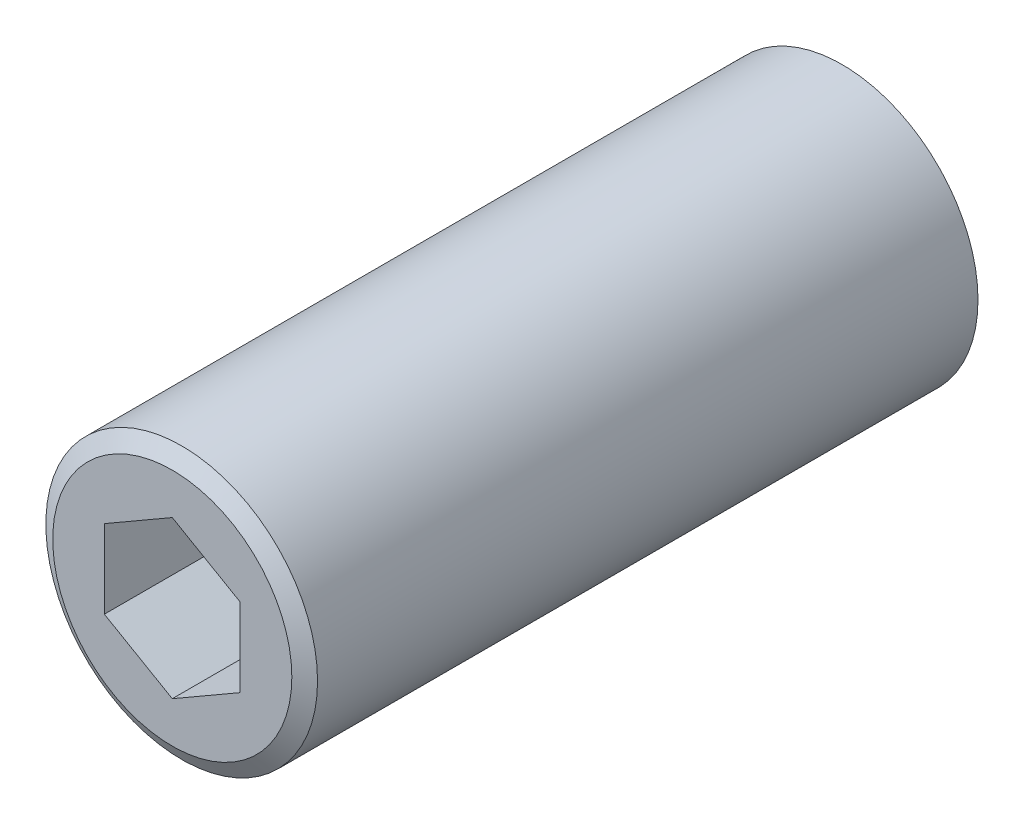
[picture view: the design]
ISO-10303-21;
HEADER;
FILE_DESCRIPTION(('STEP AP214'),'2;1');
FILE_NAME('part.step','',(''),(''),'','','');
FILE_SCHEMA(('AUTOMOTIVE_DESIGN { 1 0 10303 214 1 1 1 1 }'));
ENDSEC;
DATA;
#1=APPLICATION_CONTEXT('core data for automotive mechanical design processes');
#2=APPLICATION_PROTOCOL_DEFINITION('international standard','automotive_design',2000,#1);
#3=PRODUCT_CONTEXT('',#1,'mechanical');
#4=PRODUCT('Part','Part','',(#3));
#5=PRODUCT_RELATED_PRODUCT_CATEGORY('part','',(#4));
#6=PRODUCT_DEFINITION_FORMATION('','',#4);
#7=PRODUCT_DEFINITION_CONTEXT('part definition',#1,'design');
#8=PRODUCT_DEFINITION('design','',#6,#7);
#9=PRODUCT_DEFINITION_SHAPE('','',#8);
#10=(LENGTH_UNIT() NAMED_UNIT(*) SI_UNIT(.MILLI.,.METRE.));
#11=(NAMED_UNIT(*) PLANE_ANGLE_UNIT() SI_UNIT($,.RADIAN.));
#12=(NAMED_UNIT(*) SI_UNIT($,.STERADIAN.) SOLID_ANGLE_UNIT());
#13=UNCERTAINTY_MEASURE_WITH_UNIT(LENGTH_MEASURE(1.E-05),#10,'distance_accuracy_value','');
#14=(GEOMETRIC_REPRESENTATION_CONTEXT(3) GLOBAL_UNCERTAINTY_ASSIGNED_CONTEXT((#13)) GLOBAL_UNIT_ASSIGNED_CONTEXT((#10,
#11,#12)) REPRESENTATION_CONTEXT('',''));
#15=CARTESIAN_POINT('',(0.,0.,0.));
#16=DIRECTION('',(0.,0.,1.));
#17=DIRECTION('',(1.,0.,0.));
#18=AXIS2_PLACEMENT_3D('',#15,#16,#17);
#19=CARTESIAN_POINT('',(1.5,-6.35,0.));
#20=DIRECTION('',(-0.707106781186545,0.,0.70710678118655));
#21=DIRECTION('',(0.70710678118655,0.,0.707106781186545));
#22=AXIS2_PLACEMENT_3D('',#19,#20,#21);
#23=PLANE('',#22);
#24=CARTESIAN_POINT('',(0.,0.,-1.5));
#25=DIRECTION('',(-0.707106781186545,0.,0.70710678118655));
#26=DIRECTION('',(-0.70710678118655,0.,-0.707106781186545));
#27=AXIS2_PLACEMENT_3D('',#24,#25,#26);
#28=ELLIPSE('',#27,8.98025612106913,6.35);
#29=CARTESIAN_POINT('',(2.77,-5.71398284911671,1.27));
#30=VERTEX_POINT('',#29);
#31=CARTESIAN_POINT('',(3.,-5.59665078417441,1.5));
#32=VERTEX_POINT('',#31);
#33=EDGE_CURVE('E516',#30,#32,#28,.T.);
#34=ORIENTED_EDGE('',*,*,#33,.F.);
#35=CARTESIAN_POINT('',(0.,0.,-1.5));
#36=DIRECTION('',(-0.707106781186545,0.,0.70710678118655));
#37=DIRECTION('',(0.70710678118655,0.,0.707106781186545));
#38=AXIS2_PLACEMENT_3D('',#35,#36,#37);
#39=ELLIPSE('',#38,8.98025612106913,6.35);
#40=CARTESIAN_POINT('',(2.73216847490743,-5.73216847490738,1.2321684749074));
#41=VERTEX_POINT('',#40);
#42=EDGE_CURVE('E835',#41,#30,#39,.T.);
#43=ORIENTED_EDGE('',*,*,#42,.F.);
#44=DIRECTION('',(-0.577350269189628,0.577350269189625,-0.577350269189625));
#45=VECTOR('',#44,1.);
#46=CARTESIAN_POINT('',(2.11666666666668,-5.11666666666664,0.616666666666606));
#47=LINE('',#46,#45);
#48=CARTESIAN_POINT('',(1.49999999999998,-4.5,0.));
#49=VERTEX_POINT('',#48);
#50=EDGE_CURVE('E635',#41,#49,#47,.T.);
#51=ORIENTED_EDGE('',*,*,#50,.T.);
#52=DIRECTION('',(0.577350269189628,0.577350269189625,0.577350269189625));
#53=VECTOR('',#52,1.);
#54=CARTESIAN_POINT('',(0.883333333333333,-5.11666666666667,-0.616666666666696));
#55=LINE('',#54,#53);
#56=CARTESIAN_POINT('',(3.,-3.,1.5));
#57=VERTEX_POINT('',#56);
#58=EDGE_CURVE('E652',#49,#57,#55,.T.);
#59=ORIENTED_EDGE('',*,*,#58,.T.);
#60=DIRECTION('',(0.,1.,0.));
#61=VECTOR('',#60,1.);
#62=CARTESIAN_POINT('',(3.,-6.35,1.5));
#63=LINE('',#62,#61);
#64=EDGE_CURVE('E805',#32,#57,#63,.T.);
#65=ORIENTED_EDGE('',*,*,#64,.F.);
#66=EDGE_LOOP('',(#34,#43,#51,#59,#65));
#67=FACE_BOUND('',#66,.T.);
#68=ADVANCED_FACE('F14',(#67),#23,.F.);
#69=CARTESIAN_POINT('',(1.5,-6.35,0.));
#70=DIRECTION('',(0.707106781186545,0.,0.70710678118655));
#71=DIRECTION('',(0.70710678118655,0.,-0.707106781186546));
#72=AXIS2_PLACEMENT_3D('',#69,#70,#71);
#73=PLANE('',#72);
#74=CARTESIAN_POINT('',(0.,0.,1.5));
#75=DIRECTION('',(0.707106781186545,0.,0.70710678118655));
#76=DIRECTION('',(0.70710678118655,0.,-0.707106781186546));
#77=AXIS2_PLACEMENT_3D('',#74,#75,#76);
#78=ELLIPSE('',#77,8.98025612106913,6.35);
#79=CARTESIAN_POINT('',(0.,-6.35,1.5));
#80=VERTEX_POINT('',#79);
#81=CARTESIAN_POINT('',(0.229999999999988,-6.34583327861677,1.27));
#82=VERTEX_POINT('',#81);
#83=EDGE_CURVE('E550',#80,#82,#78,.T.);
#84=ORIENTED_EDGE('',*,*,#83,.F.);
#85=DIRECTION('',(0.,1.,0.));
#86=VECTOR('',#85,1.);
#87=CARTESIAN_POINT('',(0.,-6.35,1.5));
#88=LINE('',#87,#86);
#89=CARTESIAN_POINT('',(0.,-6.,1.5));
#90=VERTEX_POINT('',#89);
#91=EDGE_CURVE('E789',#80,#90,#88,.T.);
#92=ORIENTED_EDGE('',*,*,#91,.T.);
#93=DIRECTION('',(0.577350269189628,-0.577350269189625,-0.577350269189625));
#94=VECTOR('',#93,1.);
#95=CARTESIAN_POINT('',(1.11666666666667,-7.11666666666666,0.383333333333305));
#96=LINE('',#95,#94);
#97=CARTESIAN_POINT('',(0.340845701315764,-6.34084570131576,1.1591542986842));
#98=VERTEX_POINT('',#97);
#99=EDGE_CURVE('E625',#90,#98,#96,.T.);
#100=ORIENTED_EDGE('',*,*,#99,.T.);
#101=CARTESIAN_POINT('',(0.,0.,1.5));
#102=DIRECTION('',(0.707106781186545,0.,0.70710678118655));
#103=DIRECTION('',(-0.70710678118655,0.,0.707106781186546));
#104=AXIS2_PLACEMENT_3D('',#101,#102,#103);
#105=ELLIPSE('',#104,8.98025612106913,6.35);
#106=EDGE_CURVE('E834',#82,#98,#105,.T.);
#107=ORIENTED_EDGE('',*,*,#106,.F.);
#108=EDGE_LOOP('',(#84,#92,#100,#107));
#109=FACE_BOUND('',#108,.T.);
#110=ADVANCED_FACE('F895',(#109),#73,.F.);
#111=CARTESIAN_POINT('',(0.,0.,1.5));
#112=DIRECTION('',(0.707106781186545,0.,0.70710678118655));
#113=DIRECTION('',(0.70710678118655,0.,-0.707106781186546));
#114=AXIS2_PLACEMENT_3D('',#111,#112,#113);
#115=ELLIPSE('',#114,8.98025612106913,6.35);
#116=CARTESIAN_POINT('',(0.229999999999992,6.34583327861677,1.27));
#117=VERTEX_POINT('',#116);
#118=CARTESIAN_POINT('',(0.,6.35,1.5));
#119=VERTEX_POINT('',#118);
#120=EDGE_CURVE('E547',#117,#119,#115,.T.);
#121=ORIENTED_EDGE('',*,*,#120,.F.);
#122=CARTESIAN_POINT('',(0.340845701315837,6.34084570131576,1.15915429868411));
#123=VERTEX_POINT('',#122);
#124=EDGE_CURVE('E831',#123,#117,#105,.T.);
#125=ORIENTED_EDGE('',*,*,#124,.F.);
#126=DIRECTION('',(-0.577350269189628,-0.577350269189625,0.577350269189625));
#127=VECTOR('',#126,1.);
#128=CARTESIAN_POINT('',(-3.11666666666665,2.88333333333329,4.6166666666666));
#129=LINE('',#128,#127);
#130=CARTESIAN_POINT('',(0.,6.,1.5));
#131=VERTEX_POINT('',#130);
#132=EDGE_CURVE('E613',#123,#131,#129,.T.);
#133=ORIENTED_EDGE('',*,*,#132,.T.);
#134=EDGE_CURVE('E794',#131,#119,#88,.T.);
#135=ORIENTED_EDGE('',*,*,#134,.T.);
#136=EDGE_LOOP('',(#121,#125,#133,#135));
#137=FACE_BOUND('',#136,.T.);
#138=ADVANCED_FACE('F903',(#137),#73,.F.);
#139=CARTESIAN_POINT('',(0.,-6.35,1.5));
#140=DIRECTION('',(-0.70710678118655,0.,0.707106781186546));
#141=DIRECTION('',(0.707106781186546,0.,0.70710678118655));
#142=AXIS2_PLACEMENT_3D('',#139,#140,#141);
#143=PLANE('',#142);
#144=CARTESIAN_POINT('',(0.,0.,1.5));
#145=DIRECTION('',(-0.70710678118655,0.,0.707106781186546));
#146=DIRECTION('',(-0.707106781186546,0.,-0.70710678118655));
#147=AXIS2_PLACEMENT_3D('',#144,#145,#146);
#148=ELLIPSE('',#147,8.98025612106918,6.35);
#149=CARTESIAN_POINT('',(-0.229999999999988,-6.34583327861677,1.27));
#150=VERTEX_POINT('',#149);
#151=EDGE_CURVE('E511',#150,#80,#148,.T.);
#152=ORIENTED_EDGE('',*,*,#151,.F.);
#153=CARTESIAN_POINT('',(0.,0.,1.5));
#154=DIRECTION('',(-0.70710678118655,0.,0.707106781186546));
#155=DIRECTION('',(0.707106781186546,0.,0.70710678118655));
#156=AXIS2_PLACEMENT_3D('',#153,#154,#155);
#157=ELLIPSE('',#156,8.98025612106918,6.35);
#158=CARTESIAN_POINT('',(-0.34084570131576,-6.34084570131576,1.1591542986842));
#159=VERTEX_POINT('',#158);
#160=EDGE_CURVE('E827',#159,#150,#157,.T.);
#161=ORIENTED_EDGE('',*,*,#160,.F.);
#162=DIRECTION('',(0.577350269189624,0.577350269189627,0.577350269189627));
#163=VECTOR('',#162,1.);
#164=CARTESIAN_POINT('',(-0.116666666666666,-6.11666666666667,1.38333333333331));
#165=LINE('',#164,#163);
#166=EDGE_CURVE('E628',#159,#90,#165,.T.);
#167=ORIENTED_EDGE('',*,*,#166,.T.);
#168=ORIENTED_EDGE('',*,*,#91,.F.);
#169=EDGE_LOOP('',(#152,#161,#167,#168));
#170=FACE_BOUND('',#169,.T.);
#171=ADVANCED_FACE('F1345',(#170),#143,.F.);
#172=CARTESIAN_POINT('',(0.,0.,1.5));
#173=DIRECTION('',(-0.70710678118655,0.,0.707106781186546));
#174=DIRECTION('',(-0.707106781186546,0.,-0.70710678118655));
#175=AXIS2_PLACEMENT_3D('',#172,#173,#174);
#176=ELLIPSE('',#175,8.98025612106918,6.35);
#177=CARTESIAN_POINT('',(-0.229999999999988,6.34583327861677,1.27));
#178=VERTEX_POINT('',#177);
#179=EDGE_CURVE('E508',#119,#178,#176,.T.);
#180=ORIENTED_EDGE('',*,*,#179,.F.);
#181=ORIENTED_EDGE('',*,*,#134,.F.);
#182=DIRECTION('',(-0.577350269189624,0.577350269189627,-0.577350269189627));
#183=VECTOR('',#182,1.);
#184=CARTESIAN_POINT('',(4.11666666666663,1.88333333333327,5.6166666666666));
#185=LINE('',#184,#183);
#186=CARTESIAN_POINT('',(-0.340845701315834,6.34084570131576,1.15915429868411));
#187=VERTEX_POINT('',#186);
#188=EDGE_CURVE('E616',#131,#187,#185,.T.);
#189=ORIENTED_EDGE('',*,*,#188,.T.);
#190=EDGE_CURVE('E830',#178,#187,#157,.T.);
#191=ORIENTED_EDGE('',*,*,#190,.F.);
#192=EDGE_LOOP('',(#180,#181,#189,#191));
#193=FACE_BOUND('',#192,.T.);
#194=ADVANCED_FACE('F1341',(#193),#143,.F.);
#195=CARTESIAN_POINT('',(-1.5,-6.35,0.));
#196=DIRECTION('',(0.707106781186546,0.,0.707106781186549));
#197=DIRECTION('',(0.707106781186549,0.,-0.707106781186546));
#198=AXIS2_PLACEMENT_3D('',#195,#196,#197);
#199=PLANE('',#198);
#200=CARTESIAN_POINT('',(0.,0.,-1.5));
#201=DIRECTION('',(0.707106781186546,0.,0.707106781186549));
#202=DIRECTION('',(0.707106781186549,0.,-0.707106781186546));
#203=AXIS2_PLACEMENT_3D('',#200,#201,#202);
#204=ELLIPSE('',#203,8.98025612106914,6.35);
#205=CARTESIAN_POINT('',(-3.,-5.59665078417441,1.5));
#206=VERTEX_POINT('',#205);
#207=CARTESIAN_POINT('',(-2.77,-5.71398284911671,1.27));
#208=VERTEX_POINT('',#207);
#209=EDGE_CURVE('E37',#206,#208,#204,.T.);
#210=ORIENTED_EDGE('',*,*,#209,.F.);
#211=DIRECTION('',(0.,1.,0.));
#212=VECTOR('',#211,1.);
#213=CARTESIAN_POINT('',(-3.,-6.35,1.5));
#214=LINE('',#213,#212);
#215=CARTESIAN_POINT('',(-3.,-3.,1.5));
#216=VERTEX_POINT('',#215);
#217=EDGE_CURVE('E795',#206,#216,#214,.T.);
#218=ORIENTED_EDGE('',*,*,#217,.T.);
#219=DIRECTION('',(0.577350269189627,-0.577350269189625,-0.577350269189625));
#220=VECTOR('',#219,1.);
#221=CARTESIAN_POINT('',(-0.883333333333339,-5.11666666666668,-0.616666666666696));
#222=LINE('',#221,#220);
#223=CARTESIAN_POINT('',(-1.5,-4.49999999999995,0.));
#224=VERTEX_POINT('',#223);
#225=EDGE_CURVE('E664',#216,#224,#222,.T.);
#226=ORIENTED_EDGE('',*,*,#225,.T.);
#227=DIRECTION('',(-0.577350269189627,-0.577350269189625,0.577350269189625));
#228=VECTOR('',#227,1.);
#229=CARTESIAN_POINT('',(-2.11666666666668,-5.11666666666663,0.616666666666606));
#230=LINE('',#229,#228);
#231=CARTESIAN_POINT('',(-2.73216847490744,-5.73216847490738,1.2321684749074));
#232=VERTEX_POINT('',#231);
#233=EDGE_CURVE('E646',#224,#232,#230,.T.);
#234=ORIENTED_EDGE('',*,*,#233,.T.);
#235=CARTESIAN_POINT('',(0.,0.,-1.5));
#236=DIRECTION('',(0.707106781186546,0.,0.707106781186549));
#237=DIRECTION('',(-0.707106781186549,0.,0.707106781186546));
#238=AXIS2_PLACEMENT_3D('',#235,#236,#237);
#239=ELLIPSE('',#238,8.98025612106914,6.35);
#240=EDGE_CURVE('E826',#208,#232,#239,.T.);
#241=ORIENTED_EDGE('',*,*,#240,.F.);
#242=EDGE_LOOP('',(#210,#218,#226,#234,#241));
#243=FACE_BOUND('',#242,.T.);
#244=ADVANCED_FACE('F1335',(#243),#199,.F.);
#245=CARTESIAN_POINT('',(-3.,-6.35,1.5));
#246=DIRECTION('',(-0.707106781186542,0.,0.707106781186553));
#247=DIRECTION('',(0.707106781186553,0.,0.707106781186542));
#248=AXIS2_PLACEMENT_3D('',#245,#246,#247);
#249=PLANE('',#248);
#250=CARTESIAN_POINT('',(0.,0.,4.5));
#251=DIRECTION('',(-0.707106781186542,0.,0.707106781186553));
#252=DIRECTION('',(-0.707106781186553,0.,-0.707106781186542));
#253=AXIS2_PLACEMENT_3D('',#250,#251,#252);
#254=ELLIPSE('',#253,8.98025612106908,6.35);
#255=CARTESIAN_POINT('',(-3.23,-5.46713819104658,1.27));
#256=VERTEX_POINT('',#255);
#257=EDGE_CURVE('E543',#256,#206,#254,.T.);
#258=ORIENTED_EDGE('',*,*,#257,.F.);
#259=CARTESIAN_POINT('',(0.,0.,4.5));
#260=DIRECTION('',(-0.707106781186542,0.,0.707106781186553));
#261=DIRECTION('',(0.707106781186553,0.,0.707106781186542));
#262=AXIS2_PLACEMENT_3D('',#259,#260,#261);
#263=ELLIPSE('',#262,8.98025612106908,6.35);
#264=CARTESIAN_POINT('',(-4.49012806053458,-4.49012806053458,0.00987193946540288));
#265=VERTEX_POINT('',#264);
#266=EDGE_CURVE('E819',#265,#256,#263,.T.);
#267=ORIENTED_EDGE('',*,*,#266,.F.);
#268=DIRECTION('',(0.577350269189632,0.577350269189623,0.577350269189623));
#269=VECTOR('',#268,1.);
#270=CARTESIAN_POINT('',(-4.11666666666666,-4.11666666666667,0.383333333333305));
#271=LINE('',#270,#269);
#272=EDGE_CURVE('E666',#265,#216,#271,.T.);
#273=ORIENTED_EDGE('',*,*,#272,.T.);
#274=ORIENTED_EDGE('',*,*,#217,.F.);
#275=EDGE_LOOP('',(#258,#267,#273,#274));
#276=FACE_BOUND('',#275,.T.);
#277=ADVANCED_FACE('F1172',(#276),#249,.F.);
#278=CARTESIAN_POINT('',(-4.5,-6.35,0.));
#279=DIRECTION('',(0.707106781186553,0.,0.707106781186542));
#280=DIRECTION('',(0.707106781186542,0.,-0.707106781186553));
#281=AXIS2_PLACEMENT_3D('',#278,#279,#280);
#282=PLANE('',#281);
#283=CARTESIAN_POINT('',(0.,0.,-4.5));
#284=DIRECTION('',(0.707106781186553,0.,0.707106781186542));
#285=DIRECTION('',(0.707106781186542,0.,-0.707106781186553));
#286=AXIS2_PLACEMENT_3D('',#283,#284,#285);
#287=ELLIPSE('',#286,8.98025612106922,6.35);
#288=CARTESIAN_POINT('',(-5.77,2.65133928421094,1.27));
#289=VERTEX_POINT('',#288);
#290=CARTESIAN_POINT('',(-6.,2.07906228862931,1.5));
#291=VERTEX_POINT('',#290);
#292=EDGE_CURVE('E540',#289,#291,#287,.T.);
#293=ORIENTED_EDGE('',*,*,#292,.F.);
#294=CARTESIAN_POINT('',(0.,0.,-4.5));
#295=DIRECTION('',(0.707106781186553,0.,0.707106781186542));
#296=DIRECTION('',(-0.707106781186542,0.,0.707106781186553));
#297=AXIS2_PLACEMENT_3D('',#294,#295,#296);
#298=ELLIPSE('',#297,8.98025612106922,6.35);
#299=CARTESIAN_POINT('',(-5.73216847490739,2.73216847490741,1.2321684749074));
#300=VERTEX_POINT('',#299);
#301=EDGE_CURVE('E815',#300,#289,#298,.T.);
#302=ORIENTED_EDGE('',*,*,#301,.F.);
#303=DIRECTION('',(0.57735026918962,-0.577350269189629,-0.577350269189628));
#304=VECTOR('',#303,1.);
#305=CARTESIAN_POINT('',(-1.88333333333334,-1.1166666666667,-2.6166666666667));
#306=LINE('',#305,#304);
#307=CARTESIAN_POINT('',(-4.5,1.49999999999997,0.));
#308=VERTEX_POINT('',#307);
#309=EDGE_CURVE('E783',#300,#308,#306,.T.);
#310=ORIENTED_EDGE('',*,*,#309,.T.);
#311=DIRECTION('',(-0.57735026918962,-0.577350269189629,0.577350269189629));
#312=VECTOR('',#311,1.);
#313=CARTESIAN_POINT('',(-7.11666666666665,-1.11666666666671,2.6166666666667));
#314=LINE('',#313,#312);
#315=CARTESIAN_POINT('',(-6.,0.,1.5));
#316=VERTEX_POINT('',#315);
#317=EDGE_CURVE('E754',#308,#316,#314,.T.);
#318=ORIENTED_EDGE('',*,*,#317,.T.);
#319=DIRECTION('',(0.,1.,0.));
#320=VECTOR('',#319,1.);
#321=CARTESIAN_POINT('',(-6.,-6.35,1.5));
#322=LINE('',#321,#320);
#323=EDGE_CURVE('E801',#316,#291,#322,.T.);
#324=ORIENTED_EDGE('',*,*,#323,.T.);
#325=EDGE_LOOP('',(#293,#302,#310,#318,#324));
#326=FACE_BOUND('',#325,.T.);
#327=ADVANCED_FACE('F1219',(#326),#282,.F.);
#328=CARTESIAN_POINT('',(0.,0.,-4.5));
#329=DIRECTION('',(0.707106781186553,0.,0.707106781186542));
#330=DIRECTION('',(0.707106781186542,0.,-0.707106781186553));
#331=AXIS2_PLACEMENT_3D('',#328,#329,#330);
#332=ELLIPSE('',#331,8.98025612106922,6.35);
#333=CARTESIAN_POINT('',(-6.,-2.07906228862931,1.5));
#334=VERTEX_POINT('',#333);
#335=CARTESIAN_POINT('',(-5.77,-2.65133928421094,1.27));
#336=VERTEX_POINT('',#335);
#337=EDGE_CURVE('E534',#334,#336,#332,.T.);
#338=ORIENTED_EDGE('',*,*,#337,.F.);
#339=EDGE_CURVE('E799',#334,#316,#322,.T.);
#340=ORIENTED_EDGE('',*,*,#339,.T.);
#341=DIRECTION('',(0.57735026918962,-0.577350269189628,-0.577350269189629));
#342=VECTOR('',#341,1.);
#343=CARTESIAN_POINT('',(-2.88333333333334,-3.11666666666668,-1.6166666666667));
#344=LINE('',#343,#342);
#345=CARTESIAN_POINT('',(-4.5,-1.5,0.));
#346=VERTEX_POINT('',#345);
#347=EDGE_CURVE('E722',#316,#346,#344,.T.);
#348=ORIENTED_EDGE('',*,*,#347,.T.);
#349=DIRECTION('',(-0.57735026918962,-0.577350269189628,0.577350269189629));
#350=VECTOR('',#349,1.);
#351=CARTESIAN_POINT('',(-6.11666666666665,-3.11666666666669,1.6166666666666));
#352=LINE('',#351,#350);
#353=CARTESIAN_POINT('',(-5.73216847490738,-2.73216847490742,1.2321684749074));
#354=VERTEX_POINT('',#353);
#355=EDGE_CURVE('E693',#346,#354,#352,.T.);
#356=ORIENTED_EDGE('',*,*,#355,.T.);
#357=EDGE_CURVE('E818',#336,#354,#298,.T.);
#358=ORIENTED_EDGE('',*,*,#357,.F.);
#359=EDGE_LOOP('',(#338,#340,#348,#356,#358));
#360=FACE_BOUND('',#359,.T.);
#361=ADVANCED_FACE('F1025',(#360),#282,.F.);
#362=CARTESIAN_POINT('',(-6.,-6.35,1.5));
#363=DIRECTION('',(-0.707106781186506,0.,0.70710678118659));
#364=DIRECTION('',(0.70710678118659,0.,0.707106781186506));
#365=AXIS2_PLACEMENT_3D('',#362,#363,#364);
#366=PLANE('',#365);
#367=CARTESIAN_POINT('',(0.,0.,7.4999999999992));
#368=DIRECTION('',(-0.707106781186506,0.,0.70710678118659));
#369=DIRECTION('',(-0.70710678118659,0.,-0.707106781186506));
#370=AXIS2_PLACEMENT_3D('',#367,#368,#369);
#371=ELLIPSE('',#370,8.98025612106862,6.35);
#372=CARTESIAN_POINT('',(-6.23,1.22865780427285,1.27));
#373=VERTEX_POINT('',#372);
#374=EDGE_CURVE('E537',#291,#373,#371,.T.);
#375=ORIENTED_EDGE('',*,*,#374,.F.);
#376=ORIENTED_EDGE('',*,*,#323,.F.);
#377=DIRECTION('',(-0.577350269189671,0.577350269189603,-0.577350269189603));
#378=VECTOR('',#377,1.);
#379=CARTESIAN_POINT('',(-3.8833333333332,-2.11666666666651,3.6166666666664));
#380=LINE('',#379,#378);
#381=CARTESIAN_POINT('',(-6.34084570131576,0.340845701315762,1.1591542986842));
#382=VERTEX_POINT('',#381);
#383=EDGE_CURVE('E757',#316,#382,#380,.T.);
#384=ORIENTED_EDGE('',*,*,#383,.T.);
#385=CARTESIAN_POINT('',(0.,0.,7.4999999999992));
#386=DIRECTION('',(-0.707106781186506,0.,0.70710678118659));
#387=DIRECTION('',(0.70710678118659,0.,0.707106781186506));
#388=AXIS2_PLACEMENT_3D('',#385,#386,#387);
#389=ELLIPSE('',#388,8.98025612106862,6.35);
#390=EDGE_CURVE('E851',#373,#382,#389,.T.);
#391=ORIENTED_EDGE('',*,*,#390,.F.);
#392=EDGE_LOOP('',(#375,#376,#384,#391));
#393=FACE_BOUND('',#392,.T.);
#394=ADVANCED_FACE('F1221',(#393),#366,.F.);
#395=CARTESIAN_POINT('',(0.,0.,7.4999999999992));
#396=DIRECTION('',(-0.707106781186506,0.,0.70710678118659));
#397=DIRECTION('',(-0.70710678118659,0.,-0.707106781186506));
#398=AXIS2_PLACEMENT_3D('',#395,#396,#397);
#399=ELLIPSE('',#398,8.98025612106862,6.35);
#400=CARTESIAN_POINT('',(-6.23,-1.22865780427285,1.27));
#401=VERTEX_POINT('',#400);
#402=EDGE_CURVE('E531',#401,#334,#399,.T.);
#403=ORIENTED_EDGE('',*,*,#402,.F.);
#404=CARTESIAN_POINT('',(-6.34084570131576,-0.340845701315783,1.1591542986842));
#405=VERTEX_POINT('',#404);
#406=EDGE_CURVE('E849',#405,#401,#389,.T.);
#407=ORIENTED_EDGE('',*,*,#406,.F.);
#408=DIRECTION('',(0.577350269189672,0.577350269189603,0.577350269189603));
#409=VECTOR('',#408,1.);
#410=CARTESIAN_POINT('',(-8.1166666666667,-2.11666666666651,-0.616666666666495));
#411=LINE('',#410,#409);
#412=EDGE_CURVE('E724',#405,#316,#411,.T.);
#413=ORIENTED_EDGE('',*,*,#412,.T.);
#414=ORIENTED_EDGE('',*,*,#339,.F.);
#415=EDGE_LOOP('',(#403,#407,#413,#414));
#416=FACE_BOUND('',#415,.T.);
#417=ADVANCED_FACE('F1021',(#416),#366,.F.);
#418=CARTESIAN_POINT('',(6.,-6.35,1.5));
#419=DIRECTION('',(0.707106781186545,0.,0.70710678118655));
#420=DIRECTION('',(0.70710678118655,0.,-0.707106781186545));
#421=AXIS2_PLACEMENT_3D('',#418,#419,#420);
#422=PLANE('',#421);
#423=CARTESIAN_POINT('',(0.,0.,7.5));
#424=DIRECTION('',(0.707106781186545,0.,0.70710678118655));
#425=DIRECTION('',(0.70710678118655,0.,-0.707106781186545));
#426=AXIS2_PLACEMENT_3D('',#423,#424,#425);
#427=ELLIPSE('',#426,8.98025612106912,6.35);
#428=CARTESIAN_POINT('',(6.23,1.22865780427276,1.27));
#429=VERTEX_POINT('',#428);
#430=CARTESIAN_POINT('',(6.,2.07906228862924,1.5));
#431=VERTEX_POINT('',#430);
#432=EDGE_CURVE('E528',#429,#431,#427,.T.);
#433=ORIENTED_EDGE('',*,*,#432,.F.);
#434=CARTESIAN_POINT('',(0.,0.,7.5));
#435=DIRECTION('',(0.707106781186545,0.,0.70710678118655));
#436=DIRECTION('',(-0.70710678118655,0.,0.707106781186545));
#437=AXIS2_PLACEMENT_3D('',#434,#435,#436);
#438=ELLIPSE('',#437,8.98025612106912,6.35);
#439=CARTESIAN_POINT('',(6.34084570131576,0.340845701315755,1.1591542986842));
#440=VERTEX_POINT('',#439);
#441=EDGE_CURVE('E850',#440,#429,#438,.T.);
#442=ORIENTED_EDGE('',*,*,#441,.F.);
#443=DIRECTION('',(-0.577350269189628,-0.577350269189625,0.577350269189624));
#444=VECTOR('',#443,1.);
#445=CARTESIAN_POINT('',(3.88333333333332,-2.11666666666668,3.6166666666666));
#446=LINE('',#445,#444);
#447=CARTESIAN_POINT('',(6.,0.,1.5));
#448=VERTEX_POINT('',#447);
#449=EDGE_CURVE('E733',#440,#448,#446,.T.);
#450=ORIENTED_EDGE('',*,*,#449,.T.);
#451=DIRECTION('',(0.,1.,0.));
#452=VECTOR('',#451,1.);
#453=CARTESIAN_POINT('',(6.,-6.35,1.5));
#454=LINE('',#453,#452);
#455=EDGE_CURVE('E804',#448,#431,#454,.T.);
#456=ORIENTED_EDGE('',*,*,#455,.T.);
#457=EDGE_LOOP('',(#433,#442,#450,#456));
#458=FACE_BOUND('',#457,.T.);
#459=ADVANCED_FACE('F1917',(#458),#422,.F.);
#460=CARTESIAN_POINT('',(0.,0.,7.5));
#461=DIRECTION('',(0.707106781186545,0.,0.70710678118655));
#462=DIRECTION('',(0.70710678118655,0.,-0.707106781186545));
#463=AXIS2_PLACEMENT_3D('',#460,#461,#462);
#464=ELLIPSE('',#463,8.98025612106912,6.35);
#465=CARTESIAN_POINT('',(6.,-2.07906228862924,1.5));
#466=VERTEX_POINT('',#465);
#467=CARTESIAN_POINT('',(6.23,-1.22865780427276,1.27));
#468=VERTEX_POINT('',#467);
#469=EDGE_CURVE('E522',#466,#468,#464,.T.);
#470=ORIENTED_EDGE('',*,*,#469,.F.);
#471=EDGE_CURVE('E802',#466,#448,#454,.T.);
#472=ORIENTED_EDGE('',*,*,#471,.T.);
#473=DIRECTION('',(0.577350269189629,-0.577350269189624,-0.577350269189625));
#474=VECTOR('',#473,1.);
#475=CARTESIAN_POINT('',(8.11666666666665,-2.11666666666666,-0.616666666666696));
#476=LINE('',#475,#474);
#477=CARTESIAN_POINT('',(6.34084570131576,-0.340845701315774,1.1591542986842));
#478=VERTEX_POINT('',#477);
#479=EDGE_CURVE('E702',#448,#478,#476,.T.);
#480=ORIENTED_EDGE('',*,*,#479,.T.);
#481=EDGE_CURVE('E846',#468,#478,#438,.T.);
#482=ORIENTED_EDGE('',*,*,#481,.F.);
#483=EDGE_LOOP('',(#470,#472,#480,#482));
#484=FACE_BOUND('',#483,.T.);
#485=ADVANCED_FACE('F1913',(#484),#422,.F.);
#486=CARTESIAN_POINT('',(4.5,-6.35,0.));
#487=DIRECTION('',(-0.70710678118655,0.,0.707106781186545));
#488=DIRECTION('',(0.707106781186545,0.,0.70710678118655));
#489=AXIS2_PLACEMENT_3D('',#486,#487,#488);
#490=PLANE('',#489);
#491=CARTESIAN_POINT('',(0.,0.,-4.5));
#492=DIRECTION('',(-0.70710678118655,0.,0.707106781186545));
#493=DIRECTION('',(-0.707106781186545,0.,-0.70710678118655));
#494=AXIS2_PLACEMENT_3D('',#491,#492,#493);
#495=ELLIPSE('',#494,8.98025612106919,6.35);
#496=CARTESIAN_POINT('',(5.77,2.65133928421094,1.27));
#497=VERTEX_POINT('',#496);
#498=EDGE_CURVE('E525',#431,#497,#495,.T.);
#499=ORIENTED_EDGE('',*,*,#498,.F.);
#500=ORIENTED_EDGE('',*,*,#455,.F.);
#501=DIRECTION('',(-0.577350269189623,0.577350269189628,-0.577350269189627));
#502=VECTOR('',#501,1.);
#503=CARTESIAN_POINT('',(7.11666666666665,-1.1166666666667,2.61666666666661));
#504=LINE('',#503,#502);
#505=CARTESIAN_POINT('',(4.5,1.49999999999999,0.));
#506=VERTEX_POINT('',#505);
#507=EDGE_CURVE('E730',#448,#506,#504,.T.);
#508=ORIENTED_EDGE('',*,*,#507,.T.);
#509=DIRECTION('',(0.577350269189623,0.577350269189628,0.577350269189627));
#510=VECTOR('',#509,1.);
#511=CARTESIAN_POINT('',(1.88333333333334,-1.11666666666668,-2.6166666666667));
#512=LINE('',#511,#510);
#513=CARTESIAN_POINT('',(5.73216847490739,2.73216847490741,1.2321684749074));
#514=VERTEX_POINT('',#513);
#515=EDGE_CURVE('E763',#506,#514,#512,.T.);
#516=ORIENTED_EDGE('',*,*,#515,.T.);
#517=CARTESIAN_POINT('',(0.,0.,-4.5));
#518=DIRECTION('',(-0.70710678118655,0.,0.707106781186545));
#519=DIRECTION('',(0.707106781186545,0.,0.70710678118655));
#520=AXIS2_PLACEMENT_3D('',#517,#518,#519);
#521=ELLIPSE('',#520,8.98025612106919,6.35);
#522=EDGE_CURVE('E814',#497,#514,#521,.T.);
#523=ORIENTED_EDGE('',*,*,#522,.F.);
#524=EDGE_LOOP('',(#499,#500,#508,#516,#523));
#525=FACE_BOUND('',#524,.T.);
#526=ADVANCED_FACE('F1058',(#525),#490,.F.);
#527=CARTESIAN_POINT('',(0.,0.,-4.5));
#528=DIRECTION('',(-0.70710678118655,0.,0.707106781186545));
#529=DIRECTION('',(-0.707106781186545,0.,-0.70710678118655));
#530=AXIS2_PLACEMENT_3D('',#527,#528,#529);
#531=ELLIPSE('',#530,8.98025612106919,6.35);
#532=CARTESIAN_POINT('',(5.77,-2.65133928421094,1.27));
#533=VERTEX_POINT('',#532);
#534=EDGE_CURVE('E519',#533,#466,#531,.T.);
#535=ORIENTED_EDGE('',*,*,#534,.F.);
#536=CARTESIAN_POINT('',(5.73216847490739,-2.73216847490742,1.2321684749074));
#537=VERTEX_POINT('',#536);
#538=EDGE_CURVE('E811',#537,#533,#521,.T.);
#539=ORIENTED_EDGE('',*,*,#538,.F.);
#540=DIRECTION('',(-0.577350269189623,0.577350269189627,-0.577350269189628));
#541=VECTOR('',#540,1.);
#542=CARTESIAN_POINT('',(6.11666666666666,-3.11666666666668,1.6166666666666));
#543=LINE('',#542,#541);
#544=CARTESIAN_POINT('',(4.5,-1.5,0.));
#545=VERTEX_POINT('',#544);
#546=EDGE_CURVE('E672',#537,#545,#543,.T.);
#547=ORIENTED_EDGE('',*,*,#546,.T.);
#548=DIRECTION('',(0.577350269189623,0.577350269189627,0.577350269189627));
#549=VECTOR('',#548,1.);
#550=CARTESIAN_POINT('',(2.88333333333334,-3.11666666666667,-1.6166666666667));
#551=LINE('',#550,#549);
#552=EDGE_CURVE('E699',#545,#448,#551,.T.);
#553=ORIENTED_EDGE('',*,*,#552,.T.);
#554=ORIENTED_EDGE('',*,*,#471,.F.);
#555=EDGE_LOOP('',(#535,#539,#547,#553,#554));
#556=FACE_BOUND('',#555,.T.);
#557=ADVANCED_FACE('F958',(#556),#490,.F.);
#558=CARTESIAN_POINT('',(3.,-6.35,1.5));
#559=DIRECTION('',(0.707106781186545,0.,0.70710678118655));
#560=DIRECTION('',(0.70710678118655,0.,-0.707106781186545));
#561=AXIS2_PLACEMENT_3D('',#558,#559,#560);
#562=PLANE('',#561);
#563=CARTESIAN_POINT('',(0.,0.,4.5));
#564=DIRECTION('',(0.707106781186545,0.,0.70710678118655));
#565=DIRECTION('',(0.70710678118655,0.,-0.707106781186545));
#566=AXIS2_PLACEMENT_3D('',#563,#564,#565);
#567=ELLIPSE('',#566,8.98025612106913,6.35);
#568=CARTESIAN_POINT('',(3.23,-5.46713819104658,1.27));
#569=VERTEX_POINT('',#568);
#570=EDGE_CURVE('E513',#32,#569,#567,.T.);
#571=ORIENTED_EDGE('',*,*,#570,.F.);
#572=ORIENTED_EDGE('',*,*,#64,.T.);
#573=DIRECTION('',(0.577350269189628,-0.577350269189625,-0.577350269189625));
#574=VECTOR('',#573,1.);
#575=CARTESIAN_POINT('',(4.11666666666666,-4.11666666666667,0.383333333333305));
#576=LINE('',#575,#574);
#577=CARTESIAN_POINT('',(4.49012806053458,-4.49012806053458,0.00987193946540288));
#578=VERTEX_POINT('',#577);
#579=EDGE_CURVE('E869',#57,#578,#576,.T.);
#580=ORIENTED_EDGE('',*,*,#579,.T.);
#581=CARTESIAN_POINT('',(0.,0.,4.5));
#582=DIRECTION('',(0.707106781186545,0.,0.70710678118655));
#583=DIRECTION('',(-0.70710678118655,0.,0.707106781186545));
#584=AXIS2_PLACEMENT_3D('',#581,#582,#583);
#585=ELLIPSE('',#584,8.98025612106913,6.35);
#586=EDGE_CURVE('E810',#569,#578,#585,.T.);
#587=ORIENTED_EDGE('',*,*,#586,.F.);
#588=EDGE_LOOP('',(#571,#572,#580,#587));
#589=FACE_BOUND('',#588,.T.);
#590=ADVANCED_FACE('F911',(#589),#562,.F.);
#591=CARTESIAN_POINT('',(0.,0.,-1.5));
#592=DIRECTION('',(-0.707106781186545,0.,0.70710678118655));
#593=DIRECTION('',(-0.70710678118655,0.,-0.707106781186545));
#594=AXIS2_PLACEMENT_3D('',#591,#592,#593);
#595=ELLIPSE('',#594,8.98025612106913,6.35);
#596=CARTESIAN_POINT('',(3.,5.59665078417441,1.5));
#597=VERTEX_POINT('',#596);
#598=CARTESIAN_POINT('',(2.77,5.71398284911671,1.27));
#599=VERTEX_POINT('',#598);
#600=EDGE_CURVE('E499',#597,#599,#595,.T.);
#601=ORIENTED_EDGE('',*,*,#600,.F.);
#602=CARTESIAN_POINT('',(3.,3.,1.5));
#603=VERTEX_POINT('',#602);
#604=EDGE_CURVE('E788',#603,#597,#63,.T.);
#605=ORIENTED_EDGE('',*,*,#604,.F.);
#606=DIRECTION('',(-0.577350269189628,0.577350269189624,-0.577350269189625));
#607=VECTOR('',#606,1.);
#608=CARTESIAN_POINT('',(5.11666666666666,0.883333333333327,3.6166666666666));
#609=LINE('',#608,#607);
#610=CARTESIAN_POINT('',(1.50000000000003,4.5,0.));
#611=VERTEX_POINT('',#610);
#612=EDGE_CURVE('E556',#603,#611,#609,.T.);
#613=ORIENTED_EDGE('',*,*,#612,.T.);
#614=DIRECTION('',(0.577350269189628,0.577350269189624,0.577350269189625));
#615=VECTOR('',#614,1.);
#616=CARTESIAN_POINT('',(-2.11666666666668,0.883333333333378,-3.6166666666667));
#617=LINE('',#616,#615);
#618=CARTESIAN_POINT('',(2.73216847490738,5.73216847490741,1.23216847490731));
#619=VERTEX_POINT('',#618);
#620=EDGE_CURVE('E594',#611,#619,#617,.T.);
#621=ORIENTED_EDGE('',*,*,#620,.T.);
#622=EDGE_CURVE('E838',#599,#619,#39,.T.);
#623=ORIENTED_EDGE('',*,*,#622,.F.);
#624=EDGE_LOOP('',(#601,#605,#613,#621,#623));
#625=FACE_BOUND('',#624,.T.);
#626=ADVANCED_FACE('F898',(#625),#23,.F.);
#627=CARTESIAN_POINT('',(0.,0.,-1.5));
#628=DIRECTION('',(0.707106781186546,0.,0.707106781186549));
#629=DIRECTION('',(0.707106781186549,0.,-0.707106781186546));
#630=AXIS2_PLACEMENT_3D('',#627,#628,#629);
#631=ELLIPSE('',#630,8.98025612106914,6.35);
#632=CARTESIAN_POINT('',(-2.77,5.71398284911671,1.27));
#633=VERTEX_POINT('',#632);
#634=CARTESIAN_POINT('',(-3.,5.59665078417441,1.5));
#635=VERTEX_POINT('',#634);
#636=EDGE_CURVE('E505',#633,#635,#631,.T.);
#637=ORIENTED_EDGE('',*,*,#636,.F.);
#638=CARTESIAN_POINT('',(-2.73216847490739,5.7321684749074,1.23216847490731));
#639=VERTEX_POINT('',#638);
#640=EDGE_CURVE('E823',#639,#633,#239,.T.);
#641=ORIENTED_EDGE('',*,*,#640,.F.);
#642=DIRECTION('',(0.577350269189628,-0.577350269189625,-0.577350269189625));
#643=VECTOR('',#642,1.);
#644=CARTESIAN_POINT('',(2.11666666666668,0.883333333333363,-3.6166666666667));
#645=LINE('',#644,#643);
#646=CARTESIAN_POINT('',(-1.5,4.5,0.));
#647=VERTEX_POINT('',#646);
#648=EDGE_CURVE('E605',#639,#647,#645,.T.);
#649=ORIENTED_EDGE('',*,*,#648,.T.);
#650=DIRECTION('',(-0.577350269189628,-0.577350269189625,0.577350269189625));
#651=VECTOR('',#650,1.);
#652=CARTESIAN_POINT('',(-5.11666666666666,0.883333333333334,3.6166666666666));
#653=LINE('',#652,#651);
#654=CARTESIAN_POINT('',(-3.,3.,1.5));
#655=VERTEX_POINT('',#654);
#656=EDGE_CURVE('E584',#647,#655,#653,.T.);
#657=ORIENTED_EDGE('',*,*,#656,.T.);
#658=EDGE_CURVE('E798',#655,#635,#214,.T.);
#659=ORIENTED_EDGE('',*,*,#658,.T.);
#660=EDGE_LOOP('',(#637,#641,#649,#657,#659));
#661=FACE_BOUND('',#660,.T.);
#662=ADVANCED_FACE('F910',(#661),#199,.F.);
#663=CARTESIAN_POINT('',(0.,0.,4.5));
#664=DIRECTION('',(-0.707106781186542,0.,0.707106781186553));
#665=DIRECTION('',(-0.707106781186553,0.,-0.707106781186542));
#666=AXIS2_PLACEMENT_3D('',#663,#664,#665);
#667=ELLIPSE('',#666,8.98025612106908,6.35);
#668=CARTESIAN_POINT('',(-3.23,5.46713819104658,1.27));
#669=VERTEX_POINT('',#668);
#670=EDGE_CURVE('E502',#635,#669,#667,.T.);
#671=ORIENTED_EDGE('',*,*,#670,.F.);
#672=ORIENTED_EDGE('',*,*,#658,.F.);
#673=DIRECTION('',(-0.577350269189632,0.577350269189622,-0.577350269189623));
#674=VECTOR('',#673,1.);
#675=CARTESIAN_POINT('',(0.116666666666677,-0.116666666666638,4.6166666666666));
#676=LINE('',#675,#674);
#677=CARTESIAN_POINT('',(-4.4901280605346,4.49012806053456,0.00987193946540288));
#678=VERTEX_POINT('',#677);
#679=EDGE_CURVE('E587',#655,#678,#676,.T.);
#680=ORIENTED_EDGE('',*,*,#679,.T.);
#681=EDGE_CURVE('E822',#669,#678,#263,.T.);
#682=ORIENTED_EDGE('',*,*,#681,.F.);
#683=EDGE_LOOP('',(#671,#672,#680,#682));
#684=FACE_BOUND('',#683,.T.);
#685=ADVANCED_FACE('F1319',(#684),#249,.F.);
#686=CARTESIAN_POINT('',(0.,0.,4.5));
#687=DIRECTION('',(0.707106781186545,0.,0.70710678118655));
#688=DIRECTION('',(0.70710678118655,0.,-0.707106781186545));
#689=AXIS2_PLACEMENT_3D('',#686,#687,#688);
#690=ELLIPSE('',#689,8.98025612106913,6.35);
#691=CARTESIAN_POINT('',(3.23,5.46713819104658,1.27));
#692=VERTEX_POINT('',#691);
#693=EDGE_CURVE('E496',#692,#597,#690,.T.);
#694=ORIENTED_EDGE('',*,*,#693,.F.);
#695=CARTESIAN_POINT('',(4.4901280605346,4.49012806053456,0.00987193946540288));
#696=VERTEX_POINT('',#695);
#697=EDGE_CURVE('E792',#696,#692,#585,.T.);
#698=ORIENTED_EDGE('',*,*,#697,.F.);
#699=DIRECTION('',(-0.577350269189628,-0.577350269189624,0.577350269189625));
#700=VECTOR('',#699,1.);
#701=CARTESIAN_POINT('',(-0.116666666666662,-0.116666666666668,4.6166666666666));
#702=LINE('',#701,#700);
#703=EDGE_CURVE('E854',#696,#603,#702,.T.);
#704=ORIENTED_EDGE('',*,*,#703,.T.);
#705=ORIENTED_EDGE('',*,*,#604,.T.);
#706=EDGE_LOOP('',(#694,#698,#704,#705));
#707=FACE_BOUND('',#706,.T.);
#708=ADVANCED_FACE('F941',(#707),#562,.F.);
#709=CARTESIAN_POINT('',(6.35,3.,1.5));
#710=DIRECTION('',(0.,0.707106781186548,0.707106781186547));
#711=DIRECTION('',(0.,0.707106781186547,-0.707106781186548));
#712=AXIS2_PLACEMENT_3D('',#709,#710,#711);
#713=PLANE('',#712);
#714=CARTESIAN_POINT('',(0.,0.,4.5));
#715=DIRECTION('',(0.,0.707106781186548,0.707106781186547));
#716=DIRECTION('',(0.,0.707106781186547,-0.707106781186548));
#717=AXIS2_PLACEMENT_3D('',#714,#715,#716);
#718=ELLIPSE('',#717,8.98025612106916,6.35);
#719=CARTESIAN_POINT('',(5.59665078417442,3.,1.5));
#720=VERTEX_POINT('',#719);
#721=CARTESIAN_POINT('',(5.4671381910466,3.22999999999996,1.27));
#722=VERTEX_POINT('',#721);
#723=EDGE_CURVE('E493',#720,#722,#718,.T.);
#724=ORIENTED_EDGE('',*,*,#723,.F.);
#725=DIRECTION('',(-1.,0.,0.));
#726=VECTOR('',#725,1.);
#727=CARTESIAN_POINT('',(6.35,3.,1.5));
#728=LINE('',#727,#726);
#729=EDGE_CURVE('E570',#720,#603,#728,.T.);
#730=ORIENTED_EDGE('',*,*,#729,.T.);
#731=ORIENTED_EDGE('',*,*,#703,.F.);
#732=CARTESIAN_POINT('',(0.,0.,4.5));
#733=DIRECTION('',(0.,0.707106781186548,0.707106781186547));
#734=DIRECTION('',(0.,-0.707106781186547,0.707106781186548));
#735=AXIS2_PLACEMENT_3D('',#732,#733,#734);
#736=ELLIPSE('',#735,8.98025612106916,6.35);
#737=EDGE_CURVE('E575',#722,#696,#736,.T.);
#738=ORIENTED_EDGE('',*,*,#737,.F.);
#739=EDGE_LOOP('',(#724,#730,#731,#738));
#740=FACE_BOUND('',#739,.T.);
#741=ADVANCED_FACE('F1247',(#740),#713,.F.);
#742=CARTESIAN_POINT('',(6.35,1.49999999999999,0.));
#743=DIRECTION('',(0.,-0.707106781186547,0.707106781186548));
#744=DIRECTION('',(0.,0.707106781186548,0.707106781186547));
#745=AXIS2_PLACEMENT_3D('',#742,#743,#744);
#746=PLANE('',#745);
#747=CARTESIAN_POINT('',(0.,0.,-1.5));
#748=DIRECTION('',(0.,-0.707106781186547,0.707106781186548));
#749=DIRECTION('',(0.,-0.707106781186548,-0.707106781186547));
#750=AXIS2_PLACEMENT_3D('',#747,#748,#749);
#751=ELLIPSE('',#750,8.98025612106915,6.35);
#752=CARTESIAN_POINT('',(5.71398284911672,2.77,1.27));
#753=VERTEX_POINT('',#752);
#754=EDGE_CURVE('E490',#753,#720,#751,.T.);
#755=ORIENTED_EDGE('',*,*,#754,.F.);
#756=CARTESIAN_POINT('',(0.,0.,-1.5));
#757=DIRECTION('',(0.,-0.707106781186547,0.707106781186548));
#758=DIRECTION('',(0.,0.707106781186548,0.707106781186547));
#759=AXIS2_PLACEMENT_3D('',#756,#757,#758);
#760=ELLIPSE('',#759,8.98025612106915,6.35);
#761=EDGE_CURVE('E769',#514,#753,#760,.T.);
#762=ORIENTED_EDGE('',*,*,#761,.F.);
#763=ORIENTED_EDGE('',*,*,#515,.F.);
#764=DIRECTION('',(0.577350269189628,-0.577350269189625,-0.577350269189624));
#765=VECTOR('',#764,1.);
#766=CARTESIAN_POINT('',(6.11666666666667,-0.116666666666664,-1.6166666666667));
#767=LINE('',#766,#765);
#768=EDGE_CURVE('E857',#603,#506,#767,.T.);
#769=ORIENTED_EDGE('',*,*,#768,.F.);
#770=ORIENTED_EDGE('',*,*,#729,.F.);
#771=EDGE_LOOP('',(#755,#762,#763,#769,#770));
#772=FACE_BOUND('',#771,.T.);
#773=ADVANCED_FACE('F1065',(#772),#746,.F.);
#774=CARTESIAN_POINT('',(6.35,-3.,1.5));
#775=DIRECTION('',(0.,-0.707106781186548,0.707106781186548));
#776=DIRECTION('',(0.,0.707106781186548,0.707106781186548));
#777=AXIS2_PLACEMENT_3D('',#774,#775,#776);
#778=PLANE('',#777);
#779=CARTESIAN_POINT('',(0.,0.,4.5));
#780=DIRECTION('',(0.,-0.707106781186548,0.707106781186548));
#781=DIRECTION('',(0.,-0.707106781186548,-0.707106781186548));
#782=AXIS2_PLACEMENT_3D('',#779,#780,#781);
#783=ELLIPSE('',#782,8.98025612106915,6.35);
#784=CARTESIAN_POINT('',(5.46713819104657,-3.23,1.27));
#785=VERTEX_POINT('',#784);
#786=CARTESIAN_POINT('',(5.5966507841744,-3.,1.5));
#787=VERTEX_POINT('',#786);
#788=EDGE_CURVE('E487',#785,#787,#783,.T.);
#789=ORIENTED_EDGE('',*,*,#788,.F.);
#790=CARTESIAN_POINT('',(0.,0.,4.5));
#791=DIRECTION('',(0.,-0.707106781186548,0.707106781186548));
#792=DIRECTION('',(0.,0.707106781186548,0.707106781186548));
#793=AXIS2_PLACEMENT_3D('',#790,#791,#792);
#794=ELLIPSE('',#793,8.98025612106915,6.35);
#795=EDGE_CURVE('E655',#578,#785,#794,.T.);
#796=ORIENTED_EDGE('',*,*,#795,.F.);
#797=ORIENTED_EDGE('',*,*,#579,.F.);
#798=DIRECTION('',(-1.,0.,0.));
#799=VECTOR('',#798,1.);
#800=CARTESIAN_POINT('',(6.35,-3.,1.5));
#801=LINE('',#800,#799);
#802=EDGE_CURVE('E559',#787,#57,#801,.T.);
#803=ORIENTED_EDGE('',*,*,#802,.F.);
#804=EDGE_LOOP('',(#789,#796,#797,#803));
#805=FACE_BOUND('',#804,.T.);
#806=ADVANCED_FACE('F1149',(#805),#778,.F.);
#807=CARTESIAN_POINT('',(6.35,-1.5,0.));
#808=DIRECTION('',(0.,0.707106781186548,0.707106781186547));
#809=DIRECTION('',(0.,0.707106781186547,-0.707106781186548));
#810=AXIS2_PLACEMENT_3D('',#807,#808,#809);
#811=PLANE('',#810);
#812=CARTESIAN_POINT('',(0.,0.,-1.5));
#813=DIRECTION('',(0.,0.707106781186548,0.707106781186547));
#814=DIRECTION('',(0.,0.707106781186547,-0.707106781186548));
#815=AXIS2_PLACEMENT_3D('',#812,#813,#814);
#816=ELLIPSE('',#815,8.98025612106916,6.35);
#817=CARTESIAN_POINT('',(5.71398284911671,-2.77,1.27));
#818=VERTEX_POINT('',#817);
#819=EDGE_CURVE('E484',#787,#818,#816,.T.);
#820=ORIENTED_EDGE('',*,*,#819,.F.);
#821=ORIENTED_EDGE('',*,*,#802,.T.);
#822=DIRECTION('',(-0.577350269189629,-0.577350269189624,0.577350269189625));
#823=VECTOR('',#822,1.);
#824=CARTESIAN_POINT('',(1.88333333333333,-4.11666666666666,2.61666666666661));
#825=LINE('',#824,#823);
#826=EDGE_CURVE('E866',#545,#57,#825,.T.);
#827=ORIENTED_EDGE('',*,*,#826,.F.);
#828=ORIENTED_EDGE('',*,*,#546,.F.);
#829=CARTESIAN_POINT('',(0.,0.,-1.5));
#830=DIRECTION('',(0.,0.707106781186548,0.707106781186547));
#831=DIRECTION('',(0.,-0.707106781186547,0.707106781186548));
#832=AXIS2_PLACEMENT_3D('',#829,#830,#831);
#833=ELLIPSE('',#832,8.98025612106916,6.35);
#834=EDGE_CURVE('E678',#818,#537,#833,.T.);
#835=ORIENTED_EDGE('',*,*,#834,.F.);
#836=EDGE_LOOP('',(#820,#821,#827,#828,#835));
#837=FACE_BOUND('',#836,.T.);
#838=ADVANCED_FACE('F950',(#837),#811,.F.);
#839=CARTESIAN_POINT('',(6.35,0.,1.5));
#840=DIRECTION('',(0.,-0.707106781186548,0.707106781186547));
#841=DIRECTION('',(0.,0.707106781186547,0.707106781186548));
#842=AXIS2_PLACEMENT_3D('',#839,#840,#841);
#843=PLANE('',#842);
#844=CARTESIAN_POINT('',(0.,0.,1.5));
#845=DIRECTION('',(0.,-0.707106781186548,0.707106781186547));
#846=DIRECTION('',(0.,-0.707106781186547,-0.707106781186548));
#847=AXIS2_PLACEMENT_3D('',#844,#845,#846);
#848=ELLIPSE('',#847,8.98025612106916,6.35);
#849=CARTESIAN_POINT('',(6.34583327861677,-0.229999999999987,1.27));
#850=VERTEX_POINT('',#849);
#851=CARTESIAN_POINT('',(6.35,0.,1.5));
#852=VERTEX_POINT('',#851);
#853=EDGE_CURVE('E482',#850,#852,#848,.T.);
#854=ORIENTED_EDGE('',*,*,#853,.F.);
#855=CARTESIAN_POINT('',(0.,0.,1.5));
#856=DIRECTION('',(0.,-0.707106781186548,0.707106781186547));
#857=DIRECTION('',(0.,0.707106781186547,0.707106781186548));
#858=AXIS2_PLACEMENT_3D('',#855,#856,#857);
#859=ELLIPSE('',#858,8.98025612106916,6.35);
#860=EDGE_CURVE('E708',#478,#850,#859,.T.);
#861=ORIENTED_EDGE('',*,*,#860,.F.);
#862=ORIENTED_EDGE('',*,*,#479,.F.);
#863=DIRECTION('',(-1.,0.,0.));
#864=VECTOR('',#863,1.);
#865=CARTESIAN_POINT('',(6.35,0.,1.5));
#866=LINE('',#865,#864);
#867=EDGE_CURVE('E553',#852,#448,#866,.T.);
#868=ORIENTED_EDGE('',*,*,#867,.F.);
#869=EDGE_LOOP('',(#854,#861,#862,#868));
#870=FACE_BOUND('',#869,.T.);
#871=ADVANCED_FACE('F925',(#870),#843,.F.);
#872=CARTESIAN_POINT('',(6.35,1.49999999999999,0.));
#873=DIRECTION('',(0.,0.707106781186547,0.707106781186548));
#874=DIRECTION('',(0.,0.707106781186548,-0.707106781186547));
#875=AXIS2_PLACEMENT_3D('',#872,#873,#874);
#876=PLANE('',#875);
#877=CARTESIAN_POINT('',(0.,0.,1.5));
#878=DIRECTION('',(0.,0.707106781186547,0.707106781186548));
#879=DIRECTION('',(0.,0.707106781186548,-0.707106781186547));
#880=AXIS2_PLACEMENT_3D('',#877,#878,#879);
#881=ELLIPSE('',#880,8.98025612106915,6.35);
#882=CARTESIAN_POINT('',(6.34583327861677,0.229999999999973,1.27));
#883=VERTEX_POINT('',#882);
#884=EDGE_CURVE('E479',#852,#883,#881,.T.);
#885=ORIENTED_EDGE('',*,*,#884,.F.);
#886=ORIENTED_EDGE('',*,*,#867,.T.);
#887=ORIENTED_EDGE('',*,*,#449,.F.);
#888=CARTESIAN_POINT('',(0.,0.,1.5));
#889=DIRECTION('',(0.,0.707106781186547,0.707106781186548));
#890=DIRECTION('',(0.,-0.707106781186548,0.707106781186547));
#891=AXIS2_PLACEMENT_3D('',#888,#889,#890);
#892=ELLIPSE('',#891,8.98025612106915,6.35);
#893=EDGE_CURVE('E739',#883,#440,#892,.T.);
#894=ORIENTED_EDGE('',*,*,#893,.F.);
#895=EDGE_LOOP('',(#885,#886,#887,#894));
#896=FACE_BOUND('',#895,.T.);
#897=ADVANCED_FACE('F1325',(#896),#876,.F.);
#898=CARTESIAN_POINT('',(0.,0.,1.5));
#899=DIRECTION('',(0.,-0.707106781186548,0.707106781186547));
#900=DIRECTION('',(0.,-0.707106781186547,-0.707106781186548));
#901=AXIS2_PLACEMENT_3D('',#898,#899,#900);
#902=ELLIPSE('',#901,8.98025612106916,6.35);
#903=CARTESIAN_POINT('',(-6.35,0.,1.5));
#904=VERTEX_POINT('',#903);
#905=CARTESIAN_POINT('',(-6.34583327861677,-0.229999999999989,1.27));
#906=VERTEX_POINT('',#905);
#907=EDGE_CURVE('E476',#904,#906,#902,.T.);
#908=ORIENTED_EDGE('',*,*,#907,.F.);
#909=EDGE_CURVE('E558',#316,#904,#866,.T.);
#910=ORIENTED_EDGE('',*,*,#909,.F.);
#911=ORIENTED_EDGE('',*,*,#412,.F.);
#912=CARTESIAN_POINT('',(0.,0.,1.5));
#913=DIRECTION('',(0.,-0.707106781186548,0.707106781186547));
#914=DIRECTION('',(0.,0.707106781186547,0.707106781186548));
#915=AXIS2_PLACEMENT_3D('',#912,#913,#914);
#916=ELLIPSE('',#915,8.98025612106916,6.35);
#917=EDGE_CURVE('E727',#906,#405,#916,.T.);
#918=ORIENTED_EDGE('',*,*,#917,.F.);
#919=EDGE_LOOP('',(#908,#910,#911,#918));
#920=FACE_BOUND('',#919,.T.);
#921=ADVANCED_FACE('F1031',(#920),#843,.F.);
#922=CARTESIAN_POINT('',(0.,0.,1.5));
#923=DIRECTION('',(0.,0.707106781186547,0.707106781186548));
#924=DIRECTION('',(0.,0.707106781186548,-0.707106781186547));
#925=AXIS2_PLACEMENT_3D('',#922,#923,#924);
#926=ELLIPSE('',#925,8.98025612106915,6.35);
#927=CARTESIAN_POINT('',(-6.34583327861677,0.229999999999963,1.27));
#928=VERTEX_POINT('',#927);
#929=EDGE_CURVE('E473',#928,#904,#926,.T.);
#930=ORIENTED_EDGE('',*,*,#929,.F.);
#931=CARTESIAN_POINT('',(0.,0.,1.5));
#932=DIRECTION('',(0.,0.707106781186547,0.707106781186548));
#933=DIRECTION('',(0.,-0.707106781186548,0.707106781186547));
#934=AXIS2_PLACEMENT_3D('',#931,#932,#933);
#935=ELLIPSE('',#934,8.98025612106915,6.35);
#936=EDGE_CURVE('E760',#382,#928,#935,.T.);
#937=ORIENTED_EDGE('',*,*,#936,.F.);
#938=ORIENTED_EDGE('',*,*,#383,.F.);
#939=ORIENTED_EDGE('',*,*,#909,.T.);
#940=EDGE_LOOP('',(#930,#937,#938,#939));
#941=FACE_BOUND('',#940,.T.);
#942=ADVANCED_FACE('F1035',(#941),#876,.F.);
#943=CARTESIAN_POINT('',(0.,0.,4.5));
#944=DIRECTION('',(0.,0.707106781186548,0.707106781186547));
#945=DIRECTION('',(0.,0.707106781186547,-0.707106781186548));
#946=AXIS2_PLACEMENT_3D('',#943,#944,#945);
#947=ELLIPSE('',#946,8.98025612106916,6.35);
#948=CARTESIAN_POINT('',(-5.4671381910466,3.22999999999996,1.27));
#949=VERTEX_POINT('',#948);
#950=CARTESIAN_POINT('',(-5.59665078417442,3.,1.5));
#951=VERTEX_POINT('',#950);
#952=EDGE_CURVE('E470',#949,#951,#947,.T.);
#953=ORIENTED_EDGE('',*,*,#952,.F.);
#954=CARTESIAN_POINT('',(0.,0.,4.5));
#955=DIRECTION('',(0.,0.707106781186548,0.707106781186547));
#956=DIRECTION('',(0.,-0.707106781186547,0.707106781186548));
#957=AXIS2_PLACEMENT_3D('',#954,#955,#956);
#958=ELLIPSE('',#957,8.98025612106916,6.35);
#959=EDGE_CURVE('E590',#678,#949,#958,.T.);
#960=ORIENTED_EDGE('',*,*,#959,.F.);
#961=ORIENTED_EDGE('',*,*,#679,.F.);
#962=EDGE_CURVE('E552',#655,#951,#728,.T.);
#963=ORIENTED_EDGE('',*,*,#962,.T.);
#964=EDGE_LOOP('',(#953,#960,#961,#963));
#965=FACE_BOUND('',#964,.T.);
#966=ADVANCED_FACE('F1266',(#965),#713,.F.);
#967=CARTESIAN_POINT('',(0.,0.,-1.5));
#968=DIRECTION('',(0.,-0.707106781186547,0.707106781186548));
#969=DIRECTION('',(0.,-0.707106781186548,-0.707106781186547));
#970=AXIS2_PLACEMENT_3D('',#967,#968,#969);
#971=ELLIPSE('',#970,8.98025612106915,6.35);
#972=CARTESIAN_POINT('',(-5.71398284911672,2.77,1.27));
#973=VERTEX_POINT('',#972);
#974=EDGE_CURVE('E467',#951,#973,#971,.T.);
#975=ORIENTED_EDGE('',*,*,#974,.F.);
#976=ORIENTED_EDGE('',*,*,#962,.F.);
#977=DIRECTION('',(0.577350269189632,0.577350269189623,0.577350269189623));
#978=VECTOR('',#977,1.);
#979=CARTESIAN_POINT('',(-6.11666666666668,-0.116666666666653,-1.6166666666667));
#980=LINE('',#979,#978);
#981=EDGE_CURVE('E780',#308,#655,#980,.T.);
#982=ORIENTED_EDGE('',*,*,#981,.F.);
#983=ORIENTED_EDGE('',*,*,#309,.F.);
#984=CARTESIAN_POINT('',(0.,0.,-1.5));
#985=DIRECTION('',(0.,-0.707106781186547,0.707106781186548));
#986=DIRECTION('',(0.,0.707106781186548,0.707106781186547));
#987=AXIS2_PLACEMENT_3D('',#984,#985,#986);
#988=ELLIPSE('',#987,8.98025612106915,6.35);
#989=EDGE_CURVE('E785',#973,#300,#988,.T.);
#990=ORIENTED_EDGE('',*,*,#989,.F.);
#991=EDGE_LOOP('',(#975,#976,#982,#983,#990));
#992=FACE_BOUND('',#991,.T.);
#993=ADVANCED_FACE('F1268',(#992),#746,.F.);
#994=CARTESIAN_POINT('',(0.,0.,4.5));
#995=DIRECTION('',(0.,-0.707106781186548,0.707106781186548));
#996=DIRECTION('',(0.,-0.707106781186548,-0.707106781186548));
#997=AXIS2_PLACEMENT_3D('',#994,#995,#996);
#998=ELLIPSE('',#997,8.98025612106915,6.35);
#999=CARTESIAN_POINT('',(-5.5966507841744,-3.,1.5));
#1000=VERTEX_POINT('',#999);
#1001=CARTESIAN_POINT('',(-5.46713819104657,-3.23,1.27));
#1002=VERTEX_POINT('',#1001);
#1003=EDGE_CURVE('E464',#1000,#1002,#998,.T.);
#1004=ORIENTED_EDGE('',*,*,#1003,.F.);
#1005=EDGE_CURVE('E563',#216,#1000,#801,.T.);
#1006=ORIENTED_EDGE('',*,*,#1005,.F.);
#1007=ORIENTED_EDGE('',*,*,#272,.F.);
#1008=CARTESIAN_POINT('',(0.,0.,4.5));
#1009=DIRECTION('',(0.,-0.707106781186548,0.707106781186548));
#1010=DIRECTION('',(0.,0.707106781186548,0.707106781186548));
#1011=AXIS2_PLACEMENT_3D('',#1008,#1009,#1010);
#1012=ELLIPSE('',#1011,8.98025612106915,6.35);
#1013=EDGE_CURVE('E669',#1002,#265,#1012,.T.);
#1014=ORIENTED_EDGE('',*,*,#1013,.F.);
#1015=EDGE_LOOP('',(#1004,#1006,#1007,#1014));
#1016=FACE_BOUND('',#1015,.T.);
#1017=ADVANCED_FACE('F1365',(#1016),#778,.F.);
#1018=CARTESIAN_POINT('',(0.,0.,-1.5));
#1019=DIRECTION('',(0.,0.707106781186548,0.707106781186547));
#1020=DIRECTION('',(0.,0.707106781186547,-0.707106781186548));
#1021=AXIS2_PLACEMENT_3D('',#1018,#1019,#1020);
#1022=ELLIPSE('',#1021,8.98025612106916,6.35);
#1023=CARTESIAN_POINT('',(-5.71398284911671,-2.77,1.27));
#1024=VERTEX_POINT('',#1023);
#1025=EDGE_CURVE('E461',#1024,#1000,#1022,.T.);
#1026=ORIENTED_EDGE('',*,*,#1025,.F.);
#1027=CARTESIAN_POINT('',(0.,0.,-1.5));
#1028=DIRECTION('',(0.,0.707106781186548,0.707106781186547));
#1029=DIRECTION('',(0.,-0.707106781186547,0.707106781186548));
#1030=AXIS2_PLACEMENT_3D('',#1027,#1028,#1029);
#1031=ELLIPSE('',#1030,8.98025612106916,6.35);
#1032=EDGE_CURVE('E696',#354,#1024,#1031,.T.);
#1033=ORIENTED_EDGE('',*,*,#1032,.F.);
#1034=ORIENTED_EDGE('',*,*,#355,.F.);
#1035=DIRECTION('',(-0.577350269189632,0.577350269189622,-0.577350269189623));
#1036=VECTOR('',#1035,1.);
#1037=CARTESIAN_POINT('',(-1.88333333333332,-4.11666666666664,2.61666666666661));
#1038=LINE('',#1037,#1036);
#1039=EDGE_CURVE('E690',#216,#346,#1038,.T.);
#1040=ORIENTED_EDGE('',*,*,#1039,.F.);
#1041=ORIENTED_EDGE('',*,*,#1005,.T.);
#1042=EDGE_LOOP('',(#1026,#1033,#1034,#1040,#1041));
#1043=FACE_BOUND('',#1042,.T.);
#1044=ADVANCED_FACE('F1163',(#1043),#811,.F.);
#1045=CARTESIAN_POINT('',(6.35,4.5,0.));
#1046=DIRECTION('',(0.,-0.707106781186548,0.707106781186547));
#1047=DIRECTION('',(0.,0.707106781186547,0.707106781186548));
#1048=AXIS2_PLACEMENT_3D('',#1045,#1046,#1047);
#1049=PLANE('',#1048);
#1050=CARTESIAN_POINT('',(0.,0.,-4.5));
#1051=DIRECTION('',(0.,-0.707106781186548,0.707106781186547));
#1052=DIRECTION('',(0.,-0.707106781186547,-0.707106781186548));
#1053=AXIS2_PLACEMENT_3D('',#1050,#1051,#1052);
#1054=ELLIPSE('',#1053,8.98025612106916,6.35);
#1055=CARTESIAN_POINT('',(-2.07906228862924,6.,1.5));
#1056=VERTEX_POINT('',#1055);
#1057=CARTESIAN_POINT('',(-2.65133928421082,5.77,1.27));
#1058=VERTEX_POINT('',#1057);
#1059=EDGE_CURVE('E458',#1056,#1058,#1054,.T.);
#1060=ORIENTED_EDGE('',*,*,#1059,.F.);
#1061=DIRECTION('',(-1.,0.,0.));
#1062=VECTOR('',#1061,1.);
#1063=CARTESIAN_POINT('',(6.35,6.,1.5));
#1064=LINE('',#1063,#1062);
#1065=EDGE_CURVE('E569',#131,#1056,#1064,.T.);
#1066=ORIENTED_EDGE('',*,*,#1065,.F.);
#1067=DIRECTION('',(0.577350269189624,0.577350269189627,0.577350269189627));
#1068=VECTOR('',#1067,1.);
#1069=CARTESIAN_POINT('',(-4.11666666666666,1.88333333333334,-2.6166666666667));
#1070=LINE('',#1069,#1068);
#1071=EDGE_CURVE('E602',#647,#131,#1070,.T.);
#1072=ORIENTED_EDGE('',*,*,#1071,.F.);
#1073=ORIENTED_EDGE('',*,*,#648,.F.);
#1074=CARTESIAN_POINT('',(0.,0.,-4.5));
#1075=DIRECTION('',(0.,-0.707106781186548,0.707106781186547));
#1076=DIRECTION('',(0.,0.707106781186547,0.707106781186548));
#1077=AXIS2_PLACEMENT_3D('',#1074,#1075,#1076);
#1078=ELLIPSE('',#1077,8.98025612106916,6.35);
#1079=EDGE_CURVE('E607',#1058,#639,#1078,.T.);
#1080=ORIENTED_EDGE('',*,*,#1079,.F.);
#1081=EDGE_LOOP('',(#1060,#1066,#1072,#1073,#1080));
#1082=FACE_BOUND('',#1081,.T.);
#1083=ADVANCED_FACE('F1391',(#1082),#1049,.F.);
#1084=CARTESIAN_POINT('',(6.35,6.,1.5));
#1085=DIRECTION('',(0.,0.707106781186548,0.707106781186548));
#1086=DIRECTION('',(0.,0.707106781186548,-0.707106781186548));
#1087=AXIS2_PLACEMENT_3D('',#1084,#1085,#1086);
#1088=PLANE('',#1087);
#1089=CARTESIAN_POINT('',(0.,0.,7.5));
#1090=DIRECTION('',(0.,0.707106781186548,0.707106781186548));
#1091=DIRECTION('',(0.,0.707106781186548,-0.707106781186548));
#1092=AXIS2_PLACEMENT_3D('',#1089,#1090,#1091);
#1093=ELLIPSE('',#1092,8.98025612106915,6.35);
#1094=CARTESIAN_POINT('',(-1.22865780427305,6.22999999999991,1.27));
#1095=VERTEX_POINT('',#1094);
#1096=EDGE_CURVE('E455',#1095,#1056,#1093,.T.);
#1097=ORIENTED_EDGE('',*,*,#1096,.F.);
#1098=CARTESIAN_POINT('',(0.,0.,7.5));
#1099=DIRECTION('',(0.,0.707106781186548,0.707106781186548));
#1100=DIRECTION('',(0.,-0.707106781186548,0.707106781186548));
#1101=AXIS2_PLACEMENT_3D('',#1098,#1099,#1100);
#1102=ELLIPSE('',#1101,8.98025612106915,6.35);
#1103=EDGE_CURVE('E619',#187,#1095,#1102,.T.);
#1104=ORIENTED_EDGE('',*,*,#1103,.F.);
#1105=ORIENTED_EDGE('',*,*,#188,.F.);
#1106=ORIENTED_EDGE('',*,*,#1065,.T.);
#1107=EDGE_LOOP('',(#1097,#1104,#1105,#1106));
#1108=FACE_BOUND('',#1107,.T.);
#1109=ADVANCED_FACE('F1395',(#1108),#1088,.F.);
#1110=CARTESIAN_POINT('',(6.35,-6.,1.5));
#1111=DIRECTION('',(0.,-0.707106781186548,0.707106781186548));
#1112=DIRECTION('',(0.,0.707106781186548,0.707106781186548));
#1113=AXIS2_PLACEMENT_3D('',#1110,#1111,#1112);
#1114=PLANE('',#1113);
#1115=CARTESIAN_POINT('',(0.,0.,7.5));
#1116=DIRECTION('',(0.,-0.707106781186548,0.707106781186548));
#1117=DIRECTION('',(0.,-0.707106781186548,-0.707106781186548));
#1118=AXIS2_PLACEMENT_3D('',#1115,#1116,#1117);
#1119=ELLIPSE('',#1118,8.98025612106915,6.35);
#1120=CARTESIAN_POINT('',(-2.07906228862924,-6.,1.5));
#1121=VERTEX_POINT('',#1120);
#1122=CARTESIAN_POINT('',(-1.22865780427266,-6.23,1.27));
#1123=VERTEX_POINT('',#1122);
#1124=EDGE_CURVE('E452',#1121,#1123,#1119,.T.);
#1125=ORIENTED_EDGE('',*,*,#1124,.F.);
#1126=DIRECTION('',(-1.,0.,0.));
#1127=VECTOR('',#1126,1.);
#1128=CARTESIAN_POINT('',(6.35,-6.,1.5));
#1129=LINE('',#1128,#1127);
#1130=EDGE_CURVE('E566',#90,#1121,#1129,.T.);
#1131=ORIENTED_EDGE('',*,*,#1130,.F.);
#1132=ORIENTED_EDGE('',*,*,#166,.F.);
#1133=CARTESIAN_POINT('',(0.,0.,7.5));
#1134=DIRECTION('',(0.,-0.707106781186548,0.707106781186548));
#1135=DIRECTION('',(0.,0.707106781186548,0.707106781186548));
#1136=AXIS2_PLACEMENT_3D('',#1133,#1134,#1135);
#1137=ELLIPSE('',#1136,8.98025612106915,6.35);
#1138=EDGE_CURVE('E631',#1123,#159,#1137,.T.);
#1139=ORIENTED_EDGE('',*,*,#1138,.F.);
#1140=EDGE_LOOP('',(#1125,#1131,#1132,#1139));
#1141=FACE_BOUND('',#1140,.T.);
#1142=ADVANCED_FACE('F1837',(#1141),#1114,.F.);
#1143=CARTESIAN_POINT('',(6.35,-4.5,0.));
#1144=DIRECTION('',(0.,0.707106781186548,0.707106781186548));
#1145=DIRECTION('',(0.,0.707106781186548,-0.707106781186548));
#1146=AXIS2_PLACEMENT_3D('',#1143,#1144,#1145);
#1147=PLANE('',#1146);
#1148=CARTESIAN_POINT('',(0.,0.,-4.5));
#1149=DIRECTION('',(0.,0.707106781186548,0.707106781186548));
#1150=DIRECTION('',(0.,0.707106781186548,-0.707106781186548));
#1151=AXIS2_PLACEMENT_3D('',#1148,#1149,#1150);
#1152=ELLIPSE('',#1151,8.98025612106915,6.35);
#1153=CARTESIAN_POINT('',(-2.65133928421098,-5.77,1.27));
#1154=VERTEX_POINT('',#1153);
#1155=EDGE_CURVE('E449',#1154,#1121,#1152,.T.);
#1156=ORIENTED_EDGE('',*,*,#1155,.F.);
#1157=CARTESIAN_POINT('',(0.,0.,-4.5));
#1158=DIRECTION('',(0.,0.707106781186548,0.707106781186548));
#1159=DIRECTION('',(0.,-0.707106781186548,0.707106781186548));
#1160=AXIS2_PLACEMENT_3D('',#1157,#1158,#1159);
#1161=ELLIPSE('',#1160,8.98025612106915,6.35);
#1162=EDGE_CURVE('E649',#232,#1154,#1161,.T.);
#1163=ORIENTED_EDGE('',*,*,#1162,.F.);
#1164=ORIENTED_EDGE('',*,*,#233,.F.);
#1165=DIRECTION('',(-0.577350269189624,0.577350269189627,-0.577350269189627));
#1166=VECTOR('',#1165,1.);
#1167=CARTESIAN_POINT('',(0.11666666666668,-6.11666666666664,1.6166666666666));
#1168=LINE('',#1167,#1166);
#1169=EDGE_CURVE('E643',#90,#224,#1168,.T.);
#1170=ORIENTED_EDGE('',*,*,#1169,.F.);
#1171=ORIENTED_EDGE('',*,*,#1130,.T.);
#1172=EDGE_LOOP('',(#1156,#1163,#1164,#1170,#1171));
#1173=FACE_BOUND('',#1172,.T.);
#1174=ADVANCED_FACE('F1819',(#1173),#1147,.F.);
#1175=CARTESIAN_POINT('',(0.,0.,-4.5));
#1176=DIRECTION('',(0.,-0.707106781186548,0.707106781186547));
#1177=DIRECTION('',(0.,-0.707106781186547,-0.707106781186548));
#1178=AXIS2_PLACEMENT_3D('',#1175,#1176,#1177);
#1179=ELLIPSE('',#1178,8.98025612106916,6.35);
#1180=CARTESIAN_POINT('',(2.65133928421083,5.77,1.27));
#1181=VERTEX_POINT('',#1180);
#1182=CARTESIAN_POINT('',(2.07906228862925,6.,1.5));
#1183=VERTEX_POINT('',#1182);
#1184=EDGE_CURVE('E446',#1181,#1183,#1179,.T.);
#1185=ORIENTED_EDGE('',*,*,#1184,.F.);
#1186=CARTESIAN_POINT('',(0.,0.,-4.5));
#1187=DIRECTION('',(0.,-0.707106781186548,0.707106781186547));
#1188=DIRECTION('',(0.,0.707106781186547,0.707106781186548));
#1189=AXIS2_PLACEMENT_3D('',#1186,#1187,#1188);
#1190=ELLIPSE('',#1189,8.98025612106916,6.35);
#1191=EDGE_CURVE('E593',#619,#1181,#1190,.T.);
#1192=ORIENTED_EDGE('',*,*,#1191,.F.);
#1193=ORIENTED_EDGE('',*,*,#620,.F.);
#1194=DIRECTION('',(0.577350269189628,-0.577350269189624,-0.577350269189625));
#1195=VECTOR('',#1194,1.);
#1196=CARTESIAN_POINT('',(5.11666666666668,0.883333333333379,-3.6166666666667));
#1197=LINE('',#1196,#1195);
#1198=EDGE_CURVE('E597',#131,#611,#1197,.T.);
#1199=ORIENTED_EDGE('',*,*,#1198,.F.);
#1200=EDGE_CURVE('E567',#1183,#131,#1064,.T.);
#1201=ORIENTED_EDGE('',*,*,#1200,.F.);
#1202=EDGE_LOOP('',(#1185,#1192,#1193,#1199,#1201));
#1203=FACE_BOUND('',#1202,.T.);
#1204=ADVANCED_FACE('F1397',(#1203),#1049,.F.);
#1205=CARTESIAN_POINT('',(0.,0.,7.5));
#1206=DIRECTION('',(0.,0.707106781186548,0.707106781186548));
#1207=DIRECTION('',(0.,0.707106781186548,-0.707106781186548));
#1208=AXIS2_PLACEMENT_3D('',#1205,#1206,#1207);
#1209=ELLIPSE('',#1208,8.98025612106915,6.35);
#1210=CARTESIAN_POINT('',(1.22865780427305,6.22999999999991,1.27));
#1211=VERTEX_POINT('',#1210);
#1212=EDGE_CURVE('E443',#1183,#1211,#1209,.T.);
#1213=ORIENTED_EDGE('',*,*,#1212,.F.);
#1214=ORIENTED_EDGE('',*,*,#1200,.T.);
#1215=ORIENTED_EDGE('',*,*,#132,.F.);
#1216=CARTESIAN_POINT('',(0.,0.,7.5));
#1217=DIRECTION('',(0.,0.707106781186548,0.707106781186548));
#1218=DIRECTION('',(0.,-0.707106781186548,0.707106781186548));
#1219=AXIS2_PLACEMENT_3D('',#1216,#1217,#1218);
#1220=ELLIPSE('',#1219,8.98025612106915,6.35);
#1221=EDGE_CURVE('E610',#1211,#123,#1220,.T.);
#1222=ORIENTED_EDGE('',*,*,#1221,.F.);
#1223=EDGE_LOOP('',(#1213,#1214,#1215,#1222));
#1224=FACE_BOUND('',#1223,.T.);
#1225=ADVANCED_FACE('F1846',(#1224),#1088,.F.);
#1226=CARTESIAN_POINT('',(0.,0.,7.5));
#1227=DIRECTION('',(0.,-0.707106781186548,0.707106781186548));
#1228=DIRECTION('',(0.,-0.707106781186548,-0.707106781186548));
#1229=AXIS2_PLACEMENT_3D('',#1226,#1227,#1228);
#1230=ELLIPSE('',#1229,8.98025612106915,6.35);
#1231=CARTESIAN_POINT('',(1.22865780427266,-6.23,1.27));
#1232=VERTEX_POINT('',#1231);
#1233=CARTESIAN_POINT('',(2.07906228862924,-6.,1.5));
#1234=VERTEX_POINT('',#1233);
#1235=EDGE_CURVE('E440',#1232,#1234,#1230,.T.);
#1236=ORIENTED_EDGE('',*,*,#1235,.F.);
#1237=CARTESIAN_POINT('',(0.,0.,7.5));
#1238=DIRECTION('',(0.,-0.707106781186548,0.707106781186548));
#1239=DIRECTION('',(0.,0.707106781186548,0.707106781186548));
#1240=AXIS2_PLACEMENT_3D('',#1237,#1238,#1239);
#1241=ELLIPSE('',#1240,8.98025612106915,6.35);
#1242=EDGE_CURVE('E622',#98,#1232,#1241,.T.);
#1243=ORIENTED_EDGE('',*,*,#1242,.F.);
#1244=ORIENTED_EDGE('',*,*,#99,.F.);
#1245=EDGE_CURVE('E564',#1234,#90,#1129,.T.);
#1246=ORIENTED_EDGE('',*,*,#1245,.F.);
#1247=EDGE_LOOP('',(#1236,#1243,#1244,#1246));
#1248=FACE_BOUND('',#1247,.T.);
#1249=ADVANCED_FACE('F1826',(#1248),#1114,.F.);
#1250=CARTESIAN_POINT('',(0.,0.,-4.5));
#1251=DIRECTION('',(0.,0.707106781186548,0.707106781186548));
#1252=DIRECTION('',(0.,0.707106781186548,-0.707106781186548));
#1253=AXIS2_PLACEMENT_3D('',#1250,#1251,#1252);
#1254=ELLIPSE('',#1253,8.98025612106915,6.35);
#1255=CARTESIAN_POINT('',(2.65133928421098,-5.77,1.27));
#1256=VERTEX_POINT('',#1255);
#1257=EDGE_CURVE('E872',#1234,#1256,#1254,.T.);
#1258=ORIENTED_EDGE('',*,*,#1257,.F.);
#1259=ORIENTED_EDGE('',*,*,#1245,.T.);
#1260=DIRECTION('',(-0.577350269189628,-0.577350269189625,0.577350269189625));
#1261=VECTOR('',#1260,1.);
#1262=CARTESIAN_POINT('',(0.883333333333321,-5.11666666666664,0.616666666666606));
#1263=LINE('',#1262,#1261);
#1264=EDGE_CURVE('E638',#49,#90,#1263,.T.);
#1265=ORIENTED_EDGE('',*,*,#1264,.F.);
#1266=ORIENTED_EDGE('',*,*,#50,.F.);
#1267=CARTESIAN_POINT('',(0.,0.,-4.5));
#1268=DIRECTION('',(0.,0.707106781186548,0.707106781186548));
#1269=DIRECTION('',(0.,-0.707106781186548,0.707106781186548));
#1270=AXIS2_PLACEMENT_3D('',#1267,#1268,#1269);
#1271=ELLIPSE('',#1270,8.98025612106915,6.35);
#1272=EDGE_CURVE('E634',#1256,#41,#1271,.T.);
#1273=ORIENTED_EDGE('',*,*,#1272,.F.);
#1274=EDGE_LOOP('',(#1258,#1259,#1265,#1266,#1273));
#1275=FACE_BOUND('',#1274,.T.);
#1276=ADVANCED_FACE('F1234',(#1275),#1147,.F.);
#1277=CARTESIAN_POINT('',(0.,0.,46.27));
#1278=DIRECTION('',(0.,0.,1.));
#1279=DIRECTION('',(1.,0.,0.));
#1280=AXIS2_PLACEMENT_3D('',#1277,#1278,#1279);
#1281=CYLINDRICAL_SURFACE('',#1280,6.35);
#1282=ORIENTED_EDGE('',*,*,#240,.T.);
#1283=ORIENTED_EDGE('',*,*,#1162,.T.);
#1284=CARTESIAN_POINT('',(0.,0.,1.27));
#1285=DIRECTION('',(0.,0.,1.));
#1286=DIRECTION('',(1.,0.,0.));
#1287=AXIS2_PLACEMENT_3D('',#1284,#1285,#1286);
#1288=CIRCLE('',#1287,6.35);
#1289=EDGE_CURVE('E1124',#208,#1154,#1288,.T.);
#1290=ORIENTED_EDGE('',*,*,#1289,.F.);
#1291=EDGE_LOOP('',(#1282,#1283,#1290));
#1292=FACE_BOUND('',#1291,.T.);
#1293=ADVANCED_FACE('F1224',(#1292),#1281,.T.);
#1294=ORIENTED_EDGE('',*,*,#190,.T.);
#1295=ORIENTED_EDGE('',*,*,#1103,.T.);
#1296=EDGE_CURVE('E1107',#178,#1095,#1288,.T.);
#1297=ORIENTED_EDGE('',*,*,#1296,.F.);
#1298=EDGE_LOOP('',(#1294,#1295,#1297));
#1299=FACE_BOUND('',#1298,.T.);
#1300=ADVANCED_FACE('F1233',(#1299),#1281,.T.);
#1301=ORIENTED_EDGE('',*,*,#357,.T.);
#1302=ORIENTED_EDGE('',*,*,#1032,.T.);
#1303=EDGE_CURVE('E1008',#336,#1024,#1288,.T.);
#1304=ORIENTED_EDGE('',*,*,#1303,.F.);
#1305=EDGE_LOOP('',(#1301,#1302,#1304));
#1306=FACE_BOUND('',#1305,.T.);
#1307=ADVANCED_FACE('F1876',(#1306),#1281,.T.);
#1308=EDGE_CURVE('E844',#973,#289,#1288,.T.);
#1309=ORIENTED_EDGE('',*,*,#1308,.F.);
#1310=ORIENTED_EDGE('',*,*,#989,.T.);
#1311=ORIENTED_EDGE('',*,*,#301,.T.);
#1312=EDGE_LOOP('',(#1309,#1310,#1311));
#1313=FACE_BOUND('',#1312,.T.);
#1314=ADVANCED_FACE('F1217',(#1313),#1281,.T.);
#1315=EDGE_CURVE('E843',#883,#429,#1288,.T.);
#1316=ORIENTED_EDGE('',*,*,#1315,.F.);
#1317=ORIENTED_EDGE('',*,*,#893,.T.);
#1318=ORIENTED_EDGE('',*,*,#441,.T.);
#1319=EDGE_LOOP('',(#1316,#1317,#1318));
#1320=FACE_BOUND('',#1319,.T.);
#1321=ADVANCED_FACE('F1103',(#1320),#1281,.T.);
#1322=EDGE_CURVE('E1131',#1256,#30,#1288,.T.);
#1323=ORIENTED_EDGE('',*,*,#1322,.F.);
#1324=ORIENTED_EDGE('',*,*,#1272,.T.);
#1325=ORIENTED_EDGE('',*,*,#42,.T.);
#1326=EDGE_LOOP('',(#1323,#1324,#1325));
#1327=FACE_BOUND('',#1326,.T.);
#1328=ADVANCED_FACE('F1888',(#1327),#1281,.T.);
#1329=EDGE_CURVE('E842',#818,#533,#1288,.T.);
#1330=ORIENTED_EDGE('',*,*,#1329,.F.);
#1331=ORIENTED_EDGE('',*,*,#834,.T.);
#1332=ORIENTED_EDGE('',*,*,#538,.T.);
#1333=EDGE_LOOP('',(#1330,#1331,#1332));
#1334=FACE_BOUND('',#1333,.T.);
#1335=ADVANCED_FACE('F963',(#1334),#1281,.T.);
#1336=EDGE_CURVE('E1106',#1211,#117,#1288,.T.);
#1337=ORIENTED_EDGE('',*,*,#1336,.F.);
#1338=ORIENTED_EDGE('',*,*,#1221,.T.);
#1339=ORIENTED_EDGE('',*,*,#124,.T.);
#1340=EDGE_LOOP('',(#1337,#1338,#1339));
#1341=FACE_BOUND('',#1340,.T.);
#1342=ADVANCED_FACE('F1864',(#1341),#1281,.T.);
#1343=ORIENTED_EDGE('',*,*,#522,.T.);
#1344=ORIENTED_EDGE('',*,*,#761,.T.);
#1345=EDGE_CURVE('E845',#497,#753,#1288,.T.);
#1346=ORIENTED_EDGE('',*,*,#1345,.F.);
#1347=EDGE_LOOP('',(#1343,#1344,#1346));
#1348=FACE_BOUND('',#1347,.T.);
#1349=ADVANCED_FACE('F2165',(#1348),#1281,.T.);
#1350=EDGE_CURVE('E1011',#906,#401,#1288,.T.);
#1351=ORIENTED_EDGE('',*,*,#1350,.F.);
#1352=ORIENTED_EDGE('',*,*,#917,.T.);
#1353=ORIENTED_EDGE('',*,*,#406,.T.);
#1354=EDGE_LOOP('',(#1351,#1352,#1353));
#1355=FACE_BOUND('',#1354,.T.);
#1356=ADVANCED_FACE('F1019',(#1355),#1281,.T.);
#1357=EDGE_CURVE('E1126',#1123,#150,#1288,.T.);
#1358=ORIENTED_EDGE('',*,*,#1357,.F.);
#1359=ORIENTED_EDGE('',*,*,#1138,.T.);
#1360=ORIENTED_EDGE('',*,*,#160,.T.);
#1361=EDGE_LOOP('',(#1358,#1359,#1360));
#1362=FACE_BOUND('',#1361,.T.);
#1363=ADVANCED_FACE('F1836',(#1362),#1281,.T.);
#1364=EDGE_CURVE('E1109',#1058,#633,#1288,.T.);
#1365=ORIENTED_EDGE('',*,*,#1364,.F.);
#1366=ORIENTED_EDGE('',*,*,#1079,.T.);
#1367=ORIENTED_EDGE('',*,*,#640,.T.);
#1368=EDGE_LOOP('',(#1365,#1366,#1367));
#1369=FACE_BOUND('',#1368,.T.);
#1370=ADVANCED_FACE('F2185',(#1369),#1281,.T.);
#1371=EDGE_CURVE('E1017',#1002,#256,#1288,.T.);
#1372=ORIENTED_EDGE('',*,*,#1371,.F.);
#1373=ORIENTED_EDGE('',*,*,#1013,.T.);
#1374=ORIENTED_EDGE('',*,*,#266,.T.);
#1375=EDGE_LOOP('',(#1372,#1373,#1374));
#1376=FACE_BOUND('',#1375,.T.);
#1377=ADVANCED_FACE('F1170',(#1376),#1281,.T.);
#1378=ORIENTED_EDGE('',*,*,#681,.T.);
#1379=ORIENTED_EDGE('',*,*,#959,.T.);
#1380=EDGE_CURVE('E1111',#669,#949,#1288,.T.);
#1381=ORIENTED_EDGE('',*,*,#1380,.F.);
#1382=EDGE_LOOP('',(#1378,#1379,#1381));
#1383=FACE_BOUND('',#1382,.T.);
#1384=ADVANCED_FACE('F1905',(#1383),#1281,.T.);
#1385=ORIENTED_EDGE('',*,*,#481,.T.);
#1386=ORIENTED_EDGE('',*,*,#860,.T.);
#1387=EDGE_CURVE('E839',#468,#850,#1288,.T.);
#1388=ORIENTED_EDGE('',*,*,#1387,.F.);
#1389=EDGE_LOOP('',(#1385,#1386,#1388));
#1390=FACE_BOUND('',#1389,.T.);
#1391=ADVANCED_FACE('F1900',(#1390),#1281,.T.);
#1392=ORIENTED_EDGE('',*,*,#106,.T.);
#1393=ORIENTED_EDGE('',*,*,#1242,.T.);
#1394=EDGE_CURVE('E1128',#82,#1232,#1288,.T.);
#1395=ORIENTED_EDGE('',*,*,#1394,.F.);
#1396=EDGE_LOOP('',(#1392,#1393,#1395));
#1397=FACE_BOUND('',#1396,.T.);
#1398=ADVANCED_FACE('F1898',(#1397),#1281,.T.);
#1399=ORIENTED_EDGE('',*,*,#586,.T.);
#1400=ORIENTED_EDGE('',*,*,#795,.T.);
#1401=EDGE_CURVE('E1016',#569,#785,#1288,.T.);
#1402=ORIENTED_EDGE('',*,*,#1401,.F.);
#1403=EDGE_LOOP('',(#1399,#1400,#1402));
#1404=FACE_BOUND('',#1403,.T.);
#1405=ADVANCED_FACE('F1138',(#1404),#1281,.T.);
#1406=ORIENTED_EDGE('',*,*,#622,.T.);
#1407=ORIENTED_EDGE('',*,*,#1191,.T.);
#1408=EDGE_CURVE('E1082',#599,#1181,#1288,.T.);
#1409=ORIENTED_EDGE('',*,*,#1408,.F.);
#1410=EDGE_LOOP('',(#1406,#1407,#1409));
#1411=FACE_BOUND('',#1410,.T.);
#1412=ADVANCED_FACE('F1237',(#1411),#1281,.T.);
#1413=EDGE_CURVE('E1086',#722,#692,#1288,.T.);
#1414=ORIENTED_EDGE('',*,*,#1413,.F.);
#1415=ORIENTED_EDGE('',*,*,#737,.T.);
#1416=ORIENTED_EDGE('',*,*,#697,.T.);
#1417=EDGE_LOOP('',(#1414,#1415,#1416));
#1418=FACE_BOUND('',#1417,.T.);
#1419=ADVANCED_FACE('F1225',(#1418),#1281,.T.);
#1420=CARTESIAN_POINT('',(0.,0.,46.27));
#1421=DIRECTION('',(0.,0.,1.));
#1422=DIRECTION('',(1.,0.,0.));
#1423=AXIS2_PLACEMENT_3D('',#1420,#1421,#1422);
#1424=CYLINDRICAL_SURFACE('',#1423,10.);
#1425=CARTESIAN_POINT('',(0.,0.,50.5771796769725));
#1426=DIRECTION('',(0.,0.,1.));
#1427=DIRECTION('',(1.,0.,0.));
#1428=AXIS2_PLACEMENT_3D('',#1425,#1426,#1427);
#1429=CIRCLE('',#1428,10.);
#1430=CARTESIAN_POINT('',(10.,0.,50.5771796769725));
#1431=VERTEX_POINT('',#1430);
#1432=EDGE_CURVE('E9',#1431,#1431,#1429,.F.);
#1433=ORIENTED_EDGE('',*,*,#1432,.T.);
#1434=EDGE_LOOP('',(#1433));
#1435=FACE_BOUND('',#1434,.T.);
#1436=CARTESIAN_POINT('',(0.,0.,1.9628203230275));
#1437=DIRECTION('',(0.,0.,-1.));
#1438=DIRECTION('',(-1.,0.,0.));
#1439=AXIS2_PLACEMENT_3D('',#1436,#1437,#1438);
#1440=CIRCLE('',#1439,10.);
#1441=CARTESIAN_POINT('',(-10.,0.,1.9628203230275));
#1442=VERTEX_POINT('',#1441);
#1443=EDGE_CURVE('E875',#1442,#1442,#1440,.F.);
#1444=ORIENTED_EDGE('',*,*,#1443,.T.);
#1445=EDGE_LOOP('',(#1444));
#1446=FACE_BOUND('',#1445,.T.);
#1447=ADVANCED_FACE('F1229',(#1435,#1446),#1424,.T.);
#1448=CARTESIAN_POINT('',(10.,0.,1.27));
#1449=DIRECTION('',(0.,0.,-1.));
#1450=DIRECTION('',(-1.,0.,0.));
#1451=AXIS2_PLACEMENT_3D('',#1448,#1449,#1450);
#1452=PLANE('',#1451);
#1453=CARTESIAN_POINT('',(0.,0.,1.27));
#1454=DIRECTION('',(0.,0.,-1.));
#1455=DIRECTION('',(-1.,0.,0.));
#1456=AXIS2_PLACEMENT_3D('',#1453,#1454,#1455);
#1457=CIRCLE('',#1456,8.8);
#1458=CARTESIAN_POINT('',(-8.8,0.,1.27));
#1459=VERTEX_POINT('',#1458);
#1460=EDGE_CURVE('E878',#1459,#1459,#1457,.T.);
#1461=ORIENTED_EDGE('',*,*,#1460,.T.);
#1462=EDGE_LOOP('',(#1461));
#1463=FACE_BOUND('',#1462,.T.);
#1464=ORIENTED_EDGE('',*,*,#1322,.T.);
#1465=CARTESIAN_POINT('',(0.,0.,1.27));
#1466=DIRECTION('',(0.,0.,-1.));
#1467=DIRECTION('',(-1.,0.,0.));
#1468=AXIS2_PLACEMENT_3D('',#1465,#1466,#1467);
#1469=CIRCLE('',#1468,6.35);
#1470=EDGE_CURVE('E973',#569,#30,#1469,.T.);
#1471=ORIENTED_EDGE('',*,*,#1470,.F.);
#1472=ORIENTED_EDGE('',*,*,#1401,.T.);
#1473=EDGE_CURVE('E970',#818,#785,#1469,.T.);
#1474=ORIENTED_EDGE('',*,*,#1473,.F.);
#1475=ORIENTED_EDGE('',*,*,#1329,.T.);
#1476=EDGE_CURVE('E966',#468,#533,#1469,.T.);
#1477=ORIENTED_EDGE('',*,*,#1476,.F.);
#1478=ORIENTED_EDGE('',*,*,#1387,.T.);
#1479=EDGE_CURVE('E969',#883,#850,#1469,.T.);
#1480=ORIENTED_EDGE('',*,*,#1479,.F.);
#1481=ORIENTED_EDGE('',*,*,#1315,.T.);
#1482=EDGE_CURVE('E971',#497,#429,#1469,.T.);
#1483=ORIENTED_EDGE('',*,*,#1482,.F.);
#1484=ORIENTED_EDGE('',*,*,#1345,.T.);
#1485=EDGE_CURVE('E1088',#722,#753,#1469,.T.);
#1486=ORIENTED_EDGE('',*,*,#1485,.F.);
#1487=ORIENTED_EDGE('',*,*,#1413,.T.);
#1488=EDGE_CURVE('E1078',#599,#692,#1469,.T.);
#1489=ORIENTED_EDGE('',*,*,#1488,.F.);
#1490=ORIENTED_EDGE('',*,*,#1408,.T.);
#1491=EDGE_CURVE('E1087',#1211,#1181,#1469,.T.);
#1492=ORIENTED_EDGE('',*,*,#1491,.F.);
#1493=ORIENTED_EDGE('',*,*,#1336,.T.);
#1494=EDGE_CURVE('E1089',#178,#117,#1469,.T.);
#1495=ORIENTED_EDGE('',*,*,#1494,.F.);
#1496=ORIENTED_EDGE('',*,*,#1296,.T.);
#1497=EDGE_CURVE('E1207',#1058,#1095,#1469,.T.);
#1498=ORIENTED_EDGE('',*,*,#1497,.F.);
#1499=ORIENTED_EDGE('',*,*,#1364,.T.);
#1500=EDGE_CURVE('E1208',#669,#633,#1469,.T.);
#1501=ORIENTED_EDGE('',*,*,#1500,.F.);
#1502=ORIENTED_EDGE('',*,*,#1380,.T.);
#1503=EDGE_CURVE('E1210',#973,#949,#1469,.T.);
#1504=ORIENTED_EDGE('',*,*,#1503,.F.);
#1505=ORIENTED_EDGE('',*,*,#1308,.T.);
#1506=EDGE_CURVE('E439',#373,#289,#1469,.T.);
#1507=ORIENTED_EDGE('',*,*,#1506,.F.);
#1508=EDGE_CURVE('E1015',#373,#928,#1288,.T.);
#1509=ORIENTED_EDGE('',*,*,#1508,.T.);
#1510=EDGE_CURVE('E429',#906,#928,#1469,.T.);
#1511=ORIENTED_EDGE('',*,*,#1510,.F.);
#1512=ORIENTED_EDGE('',*,*,#1350,.T.);
#1513=EDGE_CURVE('E438',#336,#401,#1469,.T.);
#1514=ORIENTED_EDGE('',*,*,#1513,.F.);
#1515=ORIENTED_EDGE('',*,*,#1303,.T.);
#1516=EDGE_CURVE('E993',#1002,#1024,#1469,.T.);
#1517=ORIENTED_EDGE('',*,*,#1516,.F.);
#1518=ORIENTED_EDGE('',*,*,#1371,.T.);
#1519=EDGE_CURVE('E989',#208,#256,#1469,.T.);
#1520=ORIENTED_EDGE('',*,*,#1519,.F.);
#1521=ORIENTED_EDGE('',*,*,#1289,.T.);
#1522=EDGE_CURVE('E984',#1123,#1154,#1469,.T.);
#1523=ORIENTED_EDGE('',*,*,#1522,.F.);
#1524=ORIENTED_EDGE('',*,*,#1357,.T.);
#1525=EDGE_CURVE('E981',#82,#150,#1469,.T.);
#1526=ORIENTED_EDGE('',*,*,#1525,.F.);
#1527=ORIENTED_EDGE('',*,*,#1394,.T.);
#1528=EDGE_CURVE('E977',#1256,#1232,#1469,.T.);
#1529=ORIENTED_EDGE('',*,*,#1528,.F.);
#1530=EDGE_LOOP('',(#1464,#1471,#1472,#1474,#1475,#1477,#1478,#1480,#1481,#1483,#1484,#1486,
#1487,#1489,#1490,#1492,#1493,#1495,#1496,#1498,#1499,#1501,#1502,#1504,#1505,#1507,#1509,#1511,
#1512,#1514,#1515,#1517,#1518,#1520,#1521,#1523,#1524,#1526,#1527,#1529));
#1531=FACE_BOUND('',#1530,.T.);
#1532=ADVANCED_FACE('F1006',(#1463,#1531),#1452,.T.);
#1533=ORIENTED_EDGE('',*,*,#390,.T.);
#1534=ORIENTED_EDGE('',*,*,#936,.T.);
#1535=ORIENTED_EDGE('',*,*,#1508,.F.);
#1536=EDGE_LOOP('',(#1533,#1534,#1535));
#1537=FACE_BOUND('',#1536,.T.);
#1538=ADVANCED_FACE('F939',(#1537),#1281,.T.);
#1539=DIRECTION('',(0.577350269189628,-0.577350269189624,-0.577350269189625));
#1540=VECTOR('',#1539,1.);
#1541=CARTESIAN_POINT('',(5.11666666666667,-2.11666666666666,-0.616666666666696));
#1542=LINE('',#1541,#1540);
#1543=CARTESIAN_POINT('',(3.,0.,1.5));
#1544=VERTEX_POINT('',#1543);
#1545=EDGE_CURVE('E863',#1544,#545,#1542,.T.);
#1546=ORIENTED_EDGE('',*,*,#1545,.T.);
#1547=ORIENTED_EDGE('',*,*,#826,.T.);
#1548=EDGE_CURVE('E807',#57,#1544,#63,.T.);
#1549=ORIENTED_EDGE('',*,*,#1548,.T.);
#1550=EDGE_LOOP('',(#1546,#1547,#1549));
#1551=FACE_BOUND('',#1550,.T.);
#1552=ADVANCED_FACE('F929',(#1551),#562,.F.);
#1553=ORIENTED_EDGE('',*,*,#1548,.F.);
#1554=DIRECTION('',(-0.577350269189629,0.577350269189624,-0.577350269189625));
#1555=VECTOR('',#1554,1.);
#1556=CARTESIAN_POINT('',(3.11666666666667,-3.11666666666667,1.6166666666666));
#1557=LINE('',#1556,#1555);
#1558=CARTESIAN_POINT('',(1.5,-1.5,0.));
#1559=VERTEX_POINT('',#1558);
#1560=EDGE_CURVE('E675',#57,#1559,#1557,.T.);
#1561=ORIENTED_EDGE('',*,*,#1560,.T.);
#1562=DIRECTION('',(0.577350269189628,0.577350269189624,0.577350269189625));
#1563=VECTOR('',#1562,1.);
#1564=CARTESIAN_POINT('',(-0.116666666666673,-3.11666666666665,-1.6166666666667));
#1565=LINE('',#1564,#1563);
#1566=EDGE_CURVE('E705',#1559,#1544,#1565,.T.);
#1567=ORIENTED_EDGE('',*,*,#1566,.T.);
#1568=EDGE_LOOP('',(#1553,#1561,#1567));
#1569=FACE_BOUND('',#1568,.T.);
#1570=ADVANCED_FACE('F913',(#1569),#23,.F.);
#1571=ORIENTED_EDGE('',*,*,#1545,.F.);
#1572=EDGE_CURVE('E557',#448,#1544,#866,.T.);
#1573=ORIENTED_EDGE('',*,*,#1572,.F.);
#1574=ORIENTED_EDGE('',*,*,#552,.F.);
#1575=EDGE_LOOP('',(#1571,#1573,#1574));
#1576=FACE_BOUND('',#1575,.T.);
#1577=ADVANCED_FACE('F926',(#1576),#843,.F.);
#1578=ORIENTED_EDGE('',*,*,#1572,.T.);
#1579=DIRECTION('',(-0.577350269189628,-0.577350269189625,0.577350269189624));
#1580=VECTOR('',#1579,1.);
#1581=CARTESIAN_POINT('',(0.883333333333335,-2.11666666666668,3.6166666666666));
#1582=LINE('',#1581,#1580);
#1583=EDGE_CURVE('E860',#506,#1544,#1582,.T.);
#1584=ORIENTED_EDGE('',*,*,#1583,.F.);
#1585=ORIENTED_EDGE('',*,*,#507,.F.);
#1586=EDGE_LOOP('',(#1578,#1584,#1585));
#1587=FACE_BOUND('',#1586,.T.);
#1588=ADVANCED_FACE('F927',(#1587),#876,.F.);
#1589=ORIENTED_EDGE('',*,*,#768,.T.);
#1590=ORIENTED_EDGE('',*,*,#1583,.T.);
#1591=EDGE_CURVE('E946',#1544,#603,#63,.T.);
#1592=ORIENTED_EDGE('',*,*,#1591,.T.);
#1593=EDGE_LOOP('',(#1589,#1590,#1592));
#1594=FACE_BOUND('',#1593,.T.);
#1595=ADVANCED_FACE('F916',(#1594),#562,.F.);
#1596=ORIENTED_EDGE('',*,*,#1591,.F.);
#1597=DIRECTION('',(-0.577350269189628,0.577350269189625,-0.577350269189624));
#1598=VECTOR('',#1597,1.);
#1599=CARTESIAN_POINT('',(4.11666666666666,-1.11666666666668,2.61666666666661));
#1600=LINE('',#1599,#1598);
#1601=CARTESIAN_POINT('',(1.5,1.49999999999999,0.));
#1602=VERTEX_POINT('',#1601);
#1603=EDGE_CURVE('E736',#1544,#1602,#1600,.T.);
#1604=ORIENTED_EDGE('',*,*,#1603,.T.);
#1605=DIRECTION('',(0.577350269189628,0.577350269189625,0.577350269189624));
#1606=VECTOR('',#1605,1.);
#1607=CARTESIAN_POINT('',(-1.11666666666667,-1.11666666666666,-2.6166666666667));
#1608=LINE('',#1607,#1606);
#1609=EDGE_CURVE('E766',#1602,#603,#1608,.T.);
#1610=ORIENTED_EDGE('',*,*,#1609,.T.);
#1611=EDGE_LOOP('',(#1596,#1604,#1610));
#1612=FACE_BOUND('',#1611,.T.);
#1613=ADVANCED_FACE('F899',(#1612),#23,.F.);
#1614=CARTESIAN_POINT('',(-3.,0.,1.5));
#1615=VERTEX_POINT('',#1614);
#1616=EDGE_CURVE('E1034',#1615,#316,#866,.T.);
#1617=ORIENTED_EDGE('',*,*,#1616,.F.);
#1618=DIRECTION('',(0.577350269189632,0.577350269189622,0.577350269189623));
#1619=VECTOR('',#1618,1.);
#1620=CARTESIAN_POINT('',(-5.11666666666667,-2.11666666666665,-0.616666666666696));
#1621=LINE('',#1620,#1619);
#1622=EDGE_CURVE('E719',#346,#1615,#1621,.T.);
#1623=ORIENTED_EDGE('',*,*,#1622,.F.);
#1624=ORIENTED_EDGE('',*,*,#347,.F.);
#1625=EDGE_LOOP('',(#1617,#1623,#1624));
#1626=FACE_BOUND('',#1625,.T.);
#1627=ADVANCED_FACE('F915',(#1626),#843,.F.);
#1628=DIRECTION('',(-0.577350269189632,0.577350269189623,-0.577350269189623));
#1629=VECTOR('',#1628,1.);
#1630=CARTESIAN_POINT('',(-0.883333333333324,-2.11666666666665,3.6166666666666));
#1631=LINE('',#1630,#1629);
#1632=EDGE_CURVE('E751',#1615,#308,#1631,.T.);
#1633=ORIENTED_EDGE('',*,*,#1632,.F.);
#1634=ORIENTED_EDGE('',*,*,#1616,.T.);
#1635=ORIENTED_EDGE('',*,*,#317,.F.);
#1636=EDGE_LOOP('',(#1633,#1634,#1635));
#1637=FACE_BOUND('',#1636,.T.);
#1638=ADVANCED_FACE('F922',(#1637),#876,.F.);
#1639=EDGE_CURVE('E797',#216,#1615,#214,.T.);
#1640=ORIENTED_EDGE('',*,*,#1639,.F.);
#1641=ORIENTED_EDGE('',*,*,#1039,.T.);
#1642=ORIENTED_EDGE('',*,*,#1622,.T.);
#1643=EDGE_LOOP('',(#1640,#1641,#1642));
#1644=FACE_BOUND('',#1643,.T.);
#1645=ADVANCED_FACE('F1316',(#1644),#249,.F.);
#1646=DIRECTION('',(0.577350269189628,-0.577350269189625,-0.577350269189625));
#1647=VECTOR('',#1646,1.);
#1648=CARTESIAN_POINT('',(0.116666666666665,-3.11666666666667,-1.6166666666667));
#1649=LINE('',#1648,#1647);
#1650=CARTESIAN_POINT('',(-1.5,-1.5,0.));
#1651=VERTEX_POINT('',#1650);
#1652=EDGE_CURVE('E717',#1615,#1651,#1649,.T.);
#1653=ORIENTED_EDGE('',*,*,#1652,.T.);
#1654=DIRECTION('',(-0.577350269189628,-0.577350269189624,0.577350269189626));
#1655=VECTOR('',#1654,1.);
#1656=CARTESIAN_POINT('',(-3.11666666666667,-3.11666666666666,1.6166666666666));
#1657=LINE('',#1656,#1655);
#1658=EDGE_CURVE('E687',#1651,#216,#1657,.T.);
#1659=ORIENTED_EDGE('',*,*,#1658,.T.);
#1660=ORIENTED_EDGE('',*,*,#1639,.T.);
#1661=EDGE_LOOP('',(#1653,#1659,#1660));
#1662=FACE_BOUND('',#1661,.T.);
#1663=ADVANCED_FACE('F1314',(#1662),#199,.F.);
#1664=EDGE_CURVE('E1273',#1615,#655,#214,.T.);
#1665=ORIENTED_EDGE('',*,*,#1664,.F.);
#1666=ORIENTED_EDGE('',*,*,#1632,.T.);
#1667=ORIENTED_EDGE('',*,*,#981,.T.);
#1668=EDGE_LOOP('',(#1665,#1666,#1667));
#1669=FACE_BOUND('',#1668,.T.);
#1670=ADVANCED_FACE('F1271',(#1669),#249,.F.);
#1671=DIRECTION('',(0.577350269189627,-0.577350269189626,-0.577350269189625));
#1672=VECTOR('',#1671,1.);
#1673=CARTESIAN_POINT('',(1.11666666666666,-1.11666666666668,-2.6166666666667));
#1674=LINE('',#1673,#1672);
#1675=CARTESIAN_POINT('',(-1.5,1.5,0.));
#1676=VERTEX_POINT('',#1675);
#1677=EDGE_CURVE('E778',#655,#1676,#1674,.T.);
#1678=ORIENTED_EDGE('',*,*,#1677,.T.);
#1679=DIRECTION('',(-0.577350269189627,-0.577350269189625,0.577350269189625));
#1680=VECTOR('',#1679,1.);
#1681=CARTESIAN_POINT('',(-4.11666666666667,-1.11666666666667,2.61666666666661));
#1682=LINE('',#1681,#1680);
#1683=EDGE_CURVE('E748',#1676,#1615,#1682,.T.);
#1684=ORIENTED_EDGE('',*,*,#1683,.T.);
#1685=ORIENTED_EDGE('',*,*,#1664,.T.);
#1686=EDGE_LOOP('',(#1678,#1684,#1685));
#1687=FACE_BOUND('',#1686,.T.);
#1688=ADVANCED_FACE('F1275',(#1687),#199,.F.);
#1689=DIRECTION('',(-0.577350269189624,0.577350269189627,-0.577350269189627));
#1690=VECTOR('',#1689,1.);
#1691=CARTESIAN_POINT('',(3.11666666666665,-0.116666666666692,4.6166666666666));
#1692=LINE('',#1691,#1690);
#1693=CARTESIAN_POINT('',(0.,3.,1.5));
#1694=VERTEX_POINT('',#1693);
#1695=EDGE_CURVE('E581',#1694,#647,#1692,.T.);
#1696=ORIENTED_EDGE('',*,*,#1695,.F.);
#1697=EDGE_CURVE('E1257',#1694,#655,#728,.T.);
#1698=ORIENTED_EDGE('',*,*,#1697,.T.);
#1699=ORIENTED_EDGE('',*,*,#656,.F.);
#1700=EDGE_LOOP('',(#1696,#1698,#1699));
#1701=FACE_BOUND('',#1700,.T.);
#1702=ADVANCED_FACE('F1349',(#1701),#713,.F.);
#1703=ORIENTED_EDGE('',*,*,#1697,.F.);
#1704=DIRECTION('',(0.577350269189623,0.577350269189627,0.577350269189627));
#1705=VECTOR('',#1704,1.);
#1706=CARTESIAN_POINT('',(-3.11666666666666,-0.116666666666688,-1.6166666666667));
#1707=LINE('',#1706,#1705);
#1708=EDGE_CURVE('E775',#1676,#1694,#1707,.T.);
#1709=ORIENTED_EDGE('',*,*,#1708,.F.);
#1710=ORIENTED_EDGE('',*,*,#1677,.F.);
#1711=EDGE_LOOP('',(#1703,#1709,#1710));
#1712=FACE_BOUND('',#1711,.T.);
#1713=ADVANCED_FACE('F1280',(#1712),#746,.F.);
#1714=CARTESIAN_POINT('',(0.,-3.,1.5));
#1715=VERTEX_POINT('',#1714);
#1716=EDGE_CURVE('E1154',#1715,#216,#801,.T.);
#1717=ORIENTED_EDGE('',*,*,#1716,.F.);
#1718=DIRECTION('',(0.577350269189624,0.577350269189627,0.577350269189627));
#1719=VECTOR('',#1718,1.);
#1720=CARTESIAN_POINT('',(-1.11666666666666,-4.11666666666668,0.383333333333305));
#1721=LINE('',#1720,#1719);
#1722=EDGE_CURVE('E661',#224,#1715,#1721,.T.);
#1723=ORIENTED_EDGE('',*,*,#1722,.F.);
#1724=ORIENTED_EDGE('',*,*,#225,.F.);
#1725=EDGE_LOOP('',(#1717,#1723,#1724));
#1726=FACE_BOUND('',#1725,.T.);
#1727=ADVANCED_FACE('F1306',(#1726),#778,.F.);
#1728=DIRECTION('',(-0.577350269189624,0.577350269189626,-0.577350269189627));
#1729=VECTOR('',#1728,1.);
#1730=CARTESIAN_POINT('',(1.11666666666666,-4.11666666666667,2.61666666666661));
#1731=LINE('',#1730,#1729);
#1732=EDGE_CURVE('E684',#1715,#1651,#1731,.T.);
#1733=ORIENTED_EDGE('',*,*,#1732,.F.);
#1734=ORIENTED_EDGE('',*,*,#1716,.T.);
#1735=ORIENTED_EDGE('',*,*,#1658,.F.);
#1736=EDGE_LOOP('',(#1733,#1734,#1735));
#1737=FACE_BOUND('',#1736,.T.);
#1738=ADVANCED_FACE('F1307',(#1737),#811,.F.);
#1739=CARTESIAN_POINT('',(0.,0.,1.5));
#1740=VERTEX_POINT('',#1739);
#1741=EDGE_CURVE('E1045',#1740,#1615,#866,.T.);
#1742=ORIENTED_EDGE('',*,*,#1741,.F.);
#1743=DIRECTION('',(0.577350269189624,0.577350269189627,0.577350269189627));
#1744=VECTOR('',#1743,1.);
#1745=CARTESIAN_POINT('',(-2.11666666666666,-2.11666666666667,-0.616666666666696));
#1746=LINE('',#1745,#1744);
#1747=EDGE_CURVE('E714',#1651,#1740,#1746,.T.);
#1748=ORIENTED_EDGE('',*,*,#1747,.F.);
#1749=ORIENTED_EDGE('',*,*,#1652,.F.);
#1750=EDGE_LOOP('',(#1742,#1748,#1749));
#1751=FACE_BOUND('',#1750,.T.);
#1752=ADVANCED_FACE('F1311',(#1751),#843,.F.);
#1753=DIRECTION('',(-0.577350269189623,0.577350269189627,-0.577350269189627));
#1754=VECTOR('',#1753,1.);
#1755=CARTESIAN_POINT('',(2.11666666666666,-2.11666666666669,3.6166666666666));
#1756=LINE('',#1755,#1754);
#1757=EDGE_CURVE('E745',#1740,#1676,#1756,.T.);
#1758=ORIENTED_EDGE('',*,*,#1757,.F.);
#1759=ORIENTED_EDGE('',*,*,#1741,.T.);
#1760=ORIENTED_EDGE('',*,*,#1683,.F.);
#1761=EDGE_LOOP('',(#1758,#1759,#1760));
#1762=FACE_BOUND('',#1761,.T.);
#1763=ADVANCED_FACE('F1277',(#1762),#876,.F.);
#1764=ORIENTED_EDGE('',*,*,#1695,.T.);
#1765=ORIENTED_EDGE('',*,*,#1071,.T.);
#1766=EDGE_CURVE('E1288',#1694,#131,#88,.T.);
#1767=ORIENTED_EDGE('',*,*,#1766,.F.);
#1768=EDGE_LOOP('',(#1764,#1765,#1767));
#1769=FACE_BOUND('',#1768,.T.);
#1770=ADVANCED_FACE('F1415',(#1769),#143,.F.);
#1771=ORIENTED_EDGE('',*,*,#1766,.T.);
#1772=ORIENTED_EDGE('',*,*,#1198,.T.);
#1773=DIRECTION('',(-0.577350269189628,-0.577350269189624,0.577350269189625));
#1774=VECTOR('',#1773,1.);
#1775=CARTESIAN_POINT('',(-2.11666666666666,0.883333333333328,3.6166666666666));
#1776=LINE('',#1775,#1774);
#1777=EDGE_CURVE('E578',#611,#1694,#1776,.T.);
#1778=ORIENTED_EDGE('',*,*,#1777,.T.);
#1779=EDGE_LOOP('',(#1771,#1772,#1778));
#1780=FACE_BOUND('',#1779,.T.);
#1781=ADVANCED_FACE('F906',(#1780),#73,.F.);
#1782=EDGE_CURVE('E793',#90,#1715,#88,.T.);
#1783=ORIENTED_EDGE('',*,*,#1782,.F.);
#1784=ORIENTED_EDGE('',*,*,#1169,.T.);
#1785=ORIENTED_EDGE('',*,*,#1722,.T.);
#1786=EDGE_LOOP('',(#1783,#1784,#1785));
#1787=FACE_BOUND('',#1786,.T.);
#1788=ADVANCED_FACE('F1302',(#1787),#143,.F.);
#1789=DIRECTION('',(0.577350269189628,-0.577350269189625,-0.577350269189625));
#1790=VECTOR('',#1789,1.);
#1791=CARTESIAN_POINT('',(2.11666666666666,-5.11666666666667,-0.616666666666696));
#1792=LINE('',#1791,#1790);
#1793=EDGE_CURVE('E658',#1715,#49,#1792,.T.);
#1794=ORIENTED_EDGE('',*,*,#1793,.T.);
#1795=ORIENTED_EDGE('',*,*,#1264,.T.);
#1796=ORIENTED_EDGE('',*,*,#1782,.T.);
#1797=EDGE_LOOP('',(#1794,#1795,#1796));
#1798=FACE_BOUND('',#1797,.T.);
#1799=ADVANCED_FACE('F1300',(#1798),#73,.F.);
#1800=EDGE_CURVE('E1287',#1715,#1740,#88,.T.);
#1801=ORIENTED_EDGE('',*,*,#1800,.F.);
#1802=ORIENTED_EDGE('',*,*,#1732,.T.);
#1803=ORIENTED_EDGE('',*,*,#1747,.T.);
#1804=EDGE_LOOP('',(#1801,#1802,#1803));
#1805=FACE_BOUND('',#1804,.T.);
#1806=ADVANCED_FACE('F1309',(#1805),#143,.F.);
#1807=DIRECTION('',(0.577350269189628,-0.577350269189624,-0.577350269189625));
#1808=VECTOR('',#1807,1.);
#1809=CARTESIAN_POINT('',(3.11666666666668,-3.11666666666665,-1.6166666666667));
#1810=LINE('',#1809,#1808);
#1811=EDGE_CURVE('E711',#1740,#1559,#1810,.T.);
#1812=ORIENTED_EDGE('',*,*,#1811,.T.);
#1813=DIRECTION('',(-0.577350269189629,-0.577350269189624,0.577350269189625));
#1814=VECTOR('',#1813,1.);
#1815=CARTESIAN_POINT('',(-0.116666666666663,-3.11666666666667,1.6166666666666));
#1816=LINE('',#1815,#1814);
#1817=EDGE_CURVE('E681',#1559,#1715,#1816,.T.);
#1818=ORIENTED_EDGE('',*,*,#1817,.T.);
#1819=ORIENTED_EDGE('',*,*,#1800,.T.);
#1820=EDGE_LOOP('',(#1812,#1818,#1819));
#1821=FACE_BOUND('',#1820,.T.);
#1822=ADVANCED_FACE('F1294',(#1821),#73,.F.);
#1823=EDGE_CURVE('E1285',#1740,#1694,#88,.T.);
#1824=ORIENTED_EDGE('',*,*,#1823,.F.);
#1825=ORIENTED_EDGE('',*,*,#1757,.T.);
#1826=ORIENTED_EDGE('',*,*,#1708,.T.);
#1827=EDGE_LOOP('',(#1824,#1825,#1826));
#1828=FACE_BOUND('',#1827,.T.);
#1829=ADVANCED_FACE('F1283',(#1828),#143,.F.);
#1830=DIRECTION('',(0.577350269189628,-0.577350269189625,-0.577350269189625));
#1831=VECTOR('',#1830,1.);
#1832=CARTESIAN_POINT('',(4.11666666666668,-1.11666666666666,-2.6166666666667));
#1833=LINE('',#1832,#1831);
#1834=EDGE_CURVE('E772',#1694,#1602,#1833,.T.);
#1835=ORIENTED_EDGE('',*,*,#1834,.T.);
#1836=DIRECTION('',(-0.577350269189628,-0.577350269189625,0.577350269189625));
#1837=VECTOR('',#1836,1.);
#1838=CARTESIAN_POINT('',(-1.11666666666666,-1.11666666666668,2.61666666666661));
#1839=LINE('',#1838,#1837);
#1840=EDGE_CURVE('E742',#1602,#1740,#1839,.T.);
#1841=ORIENTED_EDGE('',*,*,#1840,.T.);
#1842=ORIENTED_EDGE('',*,*,#1823,.T.);
#1843=EDGE_LOOP('',(#1835,#1841,#1842));
#1844=FACE_BOUND('',#1843,.T.);
#1845=ADVANCED_FACE('F1289',(#1844),#73,.F.);
#1846=ORIENTED_EDGE('',*,*,#612,.F.);
#1847=EDGE_CURVE('E572',#603,#1694,#728,.T.);
#1848=ORIENTED_EDGE('',*,*,#1847,.T.);
#1849=ORIENTED_EDGE('',*,*,#1777,.F.);
#1850=EDGE_LOOP('',(#1846,#1848,#1849));
#1851=FACE_BOUND('',#1850,.T.);
#1852=ADVANCED_FACE('F1250',(#1851),#713,.F.);
#1853=ORIENTED_EDGE('',*,*,#1847,.F.);
#1854=ORIENTED_EDGE('',*,*,#1609,.F.);
#1855=ORIENTED_EDGE('',*,*,#1834,.F.);
#1856=EDGE_LOOP('',(#1853,#1854,#1855));
#1857=FACE_BOUND('',#1856,.T.);
#1858=ADVANCED_FACE('F1255',(#1857),#746,.F.);
#1859=EDGE_CURVE('E562',#57,#1715,#801,.T.);
#1860=ORIENTED_EDGE('',*,*,#1859,.F.);
#1861=ORIENTED_EDGE('',*,*,#58,.F.);
#1862=ORIENTED_EDGE('',*,*,#1793,.F.);
#1863=EDGE_LOOP('',(#1860,#1861,#1862));
#1864=FACE_BOUND('',#1863,.T.);
#1865=ADVANCED_FACE('F1153',(#1864),#778,.F.);
#1866=ORIENTED_EDGE('',*,*,#1560,.F.);
#1867=ORIENTED_EDGE('',*,*,#1859,.T.);
#1868=ORIENTED_EDGE('',*,*,#1817,.F.);
#1869=EDGE_LOOP('',(#1866,#1867,#1868));
#1870=FACE_BOUND('',#1869,.T.);
#1871=ADVANCED_FACE('F1152',(#1870),#811,.F.);
#1872=ORIENTED_EDGE('',*,*,#1603,.F.);
#1873=EDGE_CURVE('E1047',#1544,#1740,#866,.T.);
#1874=ORIENTED_EDGE('',*,*,#1873,.T.);
#1875=ORIENTED_EDGE('',*,*,#1840,.F.);
#1876=EDGE_LOOP('',(#1872,#1874,#1875));
#1877=FACE_BOUND('',#1876,.T.);
#1878=ADVANCED_FACE('F1290',(#1877),#876,.F.);
#1879=ORIENTED_EDGE('',*,*,#1873,.F.);
#1880=ORIENTED_EDGE('',*,*,#1566,.F.);
#1881=ORIENTED_EDGE('',*,*,#1811,.F.);
#1882=EDGE_LOOP('',(#1879,#1880,#1881));
#1883=FACE_BOUND('',#1882,.T.);
#1884=ADVANCED_FACE('F938',(#1883),#843,.F.);
#1885=CARTESIAN_POINT('',(0.,0.,13.97));
#1886=DIRECTION('',(0.,0.,-1.));
#1887=DIRECTION('',(-1.,0.,0.));
#1888=AXIS2_PLACEMENT_3D('',#1885,#1886,#1887);
#1889=CYLINDRICAL_SURFACE('',#1888,6.35);
#1890=ORIENTED_EDGE('',*,*,#1528,.T.);
#1891=ORIENTED_EDGE('',*,*,#1235,.T.);
#1892=ORIENTED_EDGE('',*,*,#1257,.T.);
#1893=EDGE_LOOP('',(#1890,#1891,#1892));
#1894=FACE_BOUND('',#1893,.T.);
#1895=ADVANCED_FACE('F1202',(#1894),#1889,.F.);
#1896=ORIENTED_EDGE('',*,*,#1473,.T.);
#1897=ORIENTED_EDGE('',*,*,#788,.T.);
#1898=ORIENTED_EDGE('',*,*,#819,.T.);
#1899=EDGE_LOOP('',(#1896,#1897,#1898));
#1900=FACE_BOUND('',#1899,.T.);
#1901=ADVANCED_FACE('F1204',(#1900),#1889,.F.);
#1902=ORIENTED_EDGE('',*,*,#1470,.T.);
#1903=ORIENTED_EDGE('',*,*,#33,.T.);
#1904=ORIENTED_EDGE('',*,*,#570,.T.);
#1905=EDGE_LOOP('',(#1902,#1903,#1904));
#1906=FACE_BOUND('',#1905,.T.);
#1907=ADVANCED_FACE('F1139',(#1906),#1889,.F.);
#1908=ORIENTED_EDGE('',*,*,#534,.T.);
#1909=ORIENTED_EDGE('',*,*,#469,.T.);
#1910=ORIENTED_EDGE('',*,*,#1476,.T.);
#1911=EDGE_LOOP('',(#1908,#1909,#1910));
#1912=FACE_BOUND('',#1911,.T.);
#1913=ADVANCED_FACE('F967',(#1912),#1889,.F.);
#1914=ORIENTED_EDGE('',*,*,#1491,.T.);
#1915=ORIENTED_EDGE('',*,*,#1184,.T.);
#1916=ORIENTED_EDGE('',*,*,#1212,.T.);
#1917=EDGE_LOOP('',(#1914,#1915,#1916));
#1918=FACE_BOUND('',#1917,.T.);
#1919=ADVANCED_FACE('F1421',(#1918),#1889,.F.);
#1920=ORIENTED_EDGE('',*,*,#754,.T.);
#1921=ORIENTED_EDGE('',*,*,#723,.T.);
#1922=ORIENTED_EDGE('',*,*,#1485,.T.);
#1923=EDGE_LOOP('',(#1920,#1921,#1922));
#1924=FACE_BOUND('',#1923,.T.);
#1925=ADVANCED_FACE('F1246',(#1924),#1889,.F.);
#1926=ORIENTED_EDGE('',*,*,#693,.T.);
#1927=ORIENTED_EDGE('',*,*,#600,.T.);
#1928=ORIENTED_EDGE('',*,*,#1488,.T.);
#1929=EDGE_LOOP('',(#1926,#1927,#1928));
#1930=FACE_BOUND('',#1929,.T.);
#1931=ADVANCED_FACE('F1077',(#1930),#1889,.F.);
#1932=ORIENTED_EDGE('',*,*,#1482,.T.);
#1933=ORIENTED_EDGE('',*,*,#432,.T.);
#1934=ORIENTED_EDGE('',*,*,#498,.T.);
#1935=EDGE_LOOP('',(#1932,#1933,#1934));
#1936=FACE_BOUND('',#1935,.T.);
#1937=ADVANCED_FACE('F1095',(#1936),#1889,.F.);
#1938=ORIENTED_EDGE('',*,*,#1155,.T.);
#1939=ORIENTED_EDGE('',*,*,#1124,.T.);
#1940=ORIENTED_EDGE('',*,*,#1522,.T.);
#1941=EDGE_LOOP('',(#1938,#1939,#1940));
#1942=FACE_BOUND('',#1941,.T.);
#1943=ADVANCED_FACE('F1186',(#1942),#1889,.F.);
#1944=ORIENTED_EDGE('',*,*,#1025,.T.);
#1945=ORIENTED_EDGE('',*,*,#1003,.T.);
#1946=ORIENTED_EDGE('',*,*,#1516,.T.);
#1947=EDGE_LOOP('',(#1944,#1945,#1946));
#1948=FACE_BOUND('',#1947,.T.);
#1949=ADVANCED_FACE('F1166',(#1948),#1889,.F.);
#1950=ORIENTED_EDGE('',*,*,#402,.T.);
#1951=ORIENTED_EDGE('',*,*,#337,.T.);
#1952=ORIENTED_EDGE('',*,*,#1513,.T.);
#1953=EDGE_LOOP('',(#1950,#1951,#1952));
#1954=FACE_BOUND('',#1953,.T.);
#1955=ADVANCED_FACE('F1002',(#1954),#1889,.F.);
#1956=ORIENTED_EDGE('',*,*,#257,.T.);
#1957=ORIENTED_EDGE('',*,*,#209,.T.);
#1958=ORIENTED_EDGE('',*,*,#1519,.T.);
#1959=EDGE_LOOP('',(#1956,#1957,#1958));
#1960=FACE_BOUND('',#1959,.T.);
#1961=ADVANCED_FACE('F1174',(#1960),#1889,.F.);
#1962=ORIENTED_EDGE('',*,*,#1096,.T.);
#1963=ORIENTED_EDGE('',*,*,#1059,.T.);
#1964=ORIENTED_EDGE('',*,*,#1497,.T.);
#1965=EDGE_LOOP('',(#1962,#1963,#1964));
#1966=FACE_BOUND('',#1965,.T.);
#1967=ADVANCED_FACE('F1176',(#1966),#1889,.F.);
#1968=ORIENTED_EDGE('',*,*,#1503,.T.);
#1969=ORIENTED_EDGE('',*,*,#952,.T.);
#1970=ORIENTED_EDGE('',*,*,#974,.T.);
#1971=EDGE_LOOP('',(#1968,#1969,#1970));
#1972=FACE_BOUND('',#1971,.T.);
#1973=ADVANCED_FACE('F1184',(#1972),#1889,.F.);
#1974=ORIENTED_EDGE('',*,*,#1500,.T.);
#1975=ORIENTED_EDGE('',*,*,#636,.T.);
#1976=ORIENTED_EDGE('',*,*,#670,.T.);
#1977=EDGE_LOOP('',(#1974,#1975,#1976));
#1978=FACE_BOUND('',#1977,.T.);
#1979=ADVANCED_FACE('F1192',(#1978),#1889,.F.);
#1980=ORIENTED_EDGE('',*,*,#1506,.T.);
#1981=ORIENTED_EDGE('',*,*,#292,.T.);
#1982=ORIENTED_EDGE('',*,*,#374,.T.);
#1983=EDGE_LOOP('',(#1980,#1981,#1982));
#1984=FACE_BOUND('',#1983,.T.);
#1985=ADVANCED_FACE('F1178',(#1984),#1889,.F.);
#1986=ORIENTED_EDGE('',*,*,#1510,.T.);
#1987=ORIENTED_EDGE('',*,*,#929,.T.);
#1988=ORIENTED_EDGE('',*,*,#907,.T.);
#1989=EDGE_LOOP('',(#1986,#1987,#1988));
#1990=FACE_BOUND('',#1989,.T.);
#1991=ADVANCED_FACE('F1191',(#1990),#1889,.F.);
#1992=ORIENTED_EDGE('',*,*,#1479,.T.);
#1993=ORIENTED_EDGE('',*,*,#853,.T.);
#1994=ORIENTED_EDGE('',*,*,#884,.T.);
#1995=EDGE_LOOP('',(#1992,#1993,#1994));
#1996=FACE_BOUND('',#1995,.T.);
#1997=ADVANCED_FACE('F1195',(#1996),#1889,.F.);
#1998=ORIENTED_EDGE('',*,*,#1494,.T.);
#1999=ORIENTED_EDGE('',*,*,#120,.T.);
#2000=ORIENTED_EDGE('',*,*,#179,.T.);
#2001=EDGE_LOOP('',(#1998,#1999,#2000));
#2002=FACE_BOUND('',#2001,.T.);
#2003=ADVANCED_FACE('F1179',(#2002),#1889,.F.);
#2004=ORIENTED_EDGE('',*,*,#1525,.T.);
#2005=ORIENTED_EDGE('',*,*,#151,.T.);
#2006=ORIENTED_EDGE('',*,*,#83,.T.);
#2007=EDGE_LOOP('',(#2004,#2005,#2006));
#2008=FACE_BOUND('',#2007,.T.);
#2009=ADVANCED_FACE('F1187',(#2008),#1889,.F.);
#2010=CARTESIAN_POINT('',(0.,0.,1.9628203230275));
#2011=DIRECTION('',(0.,0.,1.));
#2012=DIRECTION('',(1.,0.,0.));
#2013=AXIS2_PLACEMENT_3D('',#2010,#2011,#2012);
#2014=CONICAL_SURFACE('',#2013,10.,1.0471975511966);
#2015=ORIENTED_EDGE('',*,*,#1460,.F.);
#2016=EDGE_LOOP('',(#2015));
#2017=FACE_BOUND('',#2016,.T.);
#2018=ORIENTED_EDGE('',*,*,#1443,.F.);
#2019=EDGE_LOOP('',(#2018));
#2020=FACE_BOUND('',#2019,.T.);
#2021=ADVANCED_FACE('F1201',(#2017,#2020),#2014,.T.);
#2022=CARTESIAN_POINT('',(0.,0.,51.27));
#2023=DIRECTION('',(0.,0.,1.));
#2024=DIRECTION('',(1.,0.,0.));
#2025=AXIS2_PLACEMENT_3D('',#2022,#2023,#2024);
#2026=PLANE('',#2025);
#2027=CARTESIAN_POINT('',(0.,0.,51.27));
#2028=DIRECTION('',(0.,0.,1.));
#2029=DIRECTION('',(1.,0.,0.));
#2030=AXIS2_PLACEMENT_3D('',#2027,#2028,#2029);
#2031=CIRCLE('',#2030,8.8);
#2032=CARTESIAN_POINT('',(8.8,0.,51.27));
#2033=VERTEX_POINT('',#2032);
#2034=EDGE_CURVE('E22',#2033,#2033,#2031,.T.);
#2035=ORIENTED_EDGE('',*,*,#2034,.T.);
#2036=EDGE_LOOP('',(#2035));
#2037=FACE_BOUND('',#2036,.T.);
#2038=DIRECTION('',(-0.866025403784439,0.5,0.));
#2039=VECTOR('',#2038,1.);
#2040=CARTESIAN_POINT('',(5.,2.88675134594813,51.27));
#2041=LINE('',#2040,#2039);
#2042=CARTESIAN_POINT('',(5.,2.88675134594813,51.27));
#2043=VERTEX_POINT('',#2042);
#2044=CARTESIAN_POINT('',(0.,5.77350269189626,51.27));
#2045=VERTEX_POINT('',#2044);
#2046=EDGE_CURVE('E29',#2043,#2045,#2041,.T.);
#2047=ORIENTED_EDGE('',*,*,#2046,.F.);
#2048=DIRECTION('',(0.,1.,0.));
#2049=VECTOR('',#2048,1.);
#2050=CARTESIAN_POINT('',(5.,-2.88675134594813,51.27));
#2051=LINE('',#2050,#2049);
#2052=CARTESIAN_POINT('',(5.,-2.88675134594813,51.27));
#2053=VERTEX_POINT('',#2052);
#2054=EDGE_CURVE('E403',#2053,#2043,#2051,.T.);
#2055=ORIENTED_EDGE('',*,*,#2054,.F.);
#2056=DIRECTION('',(0.866025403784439,0.5,0.));
#2057=VECTOR('',#2056,1.);
#2058=CARTESIAN_POINT('',(0.,-5.77350269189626,51.27));
#2059=LINE('',#2058,#2057);
#2060=CARTESIAN_POINT('',(0.,-5.77350269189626,51.27));
#2061=VERTEX_POINT('',#2060);
#2062=EDGE_CURVE('E406',#2061,#2053,#2059,.T.);
#2063=ORIENTED_EDGE('',*,*,#2062,.F.);
#2064=DIRECTION('',(0.866025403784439,-0.5,0.));
#2065=VECTOR('',#2064,1.);
#2066=CARTESIAN_POINT('',(-5.,-2.88675134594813,51.27));
#2067=LINE('',#2066,#2065);
#2068=CARTESIAN_POINT('',(-5.,-2.88675134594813,51.27));
#2069=VERTEX_POINT('',#2068);
#2070=EDGE_CURVE('E422',#2069,#2061,#2067,.T.);
#2071=ORIENTED_EDGE('',*,*,#2070,.F.);
#2072=DIRECTION('',(0.,-1.,0.));
#2073=VECTOR('',#2072,1.);
#2074=CARTESIAN_POINT('',(-5.,2.88675134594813,51.27));
#2075=LINE('',#2074,#2073);
#2076=CARTESIAN_POINT('',(-5.,2.88675134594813,51.27));
#2077=VERTEX_POINT('',#2076);
#2078=EDGE_CURVE('E419',#2077,#2069,#2075,.T.);
#2079=ORIENTED_EDGE('',*,*,#2078,.F.);
#2080=DIRECTION('',(-0.866025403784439,-0.5,0.));
#2081=VECTOR('',#2080,1.);
#2082=CARTESIAN_POINT('',(0.,5.77350269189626,51.27));
#2083=LINE('',#2082,#2081);
#2084=EDGE_CURVE('E417',#2045,#2077,#2083,.T.);
#2085=ORIENTED_EDGE('',*,*,#2084,.F.);
#2086=EDGE_LOOP('',(#2047,#2055,#2063,#2071,#2079,#2085));
#2087=FACE_BOUND('',#2086,.T.);
#2088=ADVANCED_FACE('F883',(#2037,#2087),#2026,.T.);
#2089=CARTESIAN_POINT('',(5.,2.88675134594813,43.27));
#2090=DIRECTION('',(0.5,0.866025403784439,0.));
#2091=DIRECTION('',(0.866025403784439,-0.5,0.));
#2092=AXIS2_PLACEMENT_3D('',#2089,#2090,#2091);
#2093=PLANE('',#2092);
#2094=ORIENTED_EDGE('',*,*,#2046,.T.);
#2095=DIRECTION('',(0.,0.,1.));
#2096=VECTOR('',#2095,1.);
#2097=CARTESIAN_POINT('',(0.,5.77350269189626,43.27));
#2098=LINE('',#2097,#2096);
#2099=CARTESIAN_POINT('',(0.,5.77350269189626,43.27));
#2100=VERTEX_POINT('',#2099);
#2101=EDGE_CURVE('E380',#2100,#2045,#2098,.T.);
#2102=ORIENTED_EDGE('',*,*,#2101,.F.);
#2103=DIRECTION('',(-0.866025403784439,0.5,0.));
#2104=VECTOR('',#2103,1.);
#2105=CARTESIAN_POINT('',(5.,2.88675134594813,43.27));
#2106=LINE('',#2105,#2104);
#2107=CARTESIAN_POINT('',(5.,2.88675134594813,43.27));
#2108=VERTEX_POINT('',#2107);
#2109=EDGE_CURVE('E384',#2108,#2100,#2106,.T.);
#2110=ORIENTED_EDGE('',*,*,#2109,.F.);
#2111=DIRECTION('',(0.,0.,1.));
#2112=VECTOR('',#2111,1.);
#2113=CARTESIAN_POINT('',(5.,2.88675134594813,43.27));
#2114=LINE('',#2113,#2112);
#2115=EDGE_CURVE('E427',#2108,#2043,#2114,.T.);
#2116=ORIENTED_EDGE('',*,*,#2115,.T.);
#2117=EDGE_LOOP('',(#2094,#2102,#2110,#2116));
#2118=FACE_BOUND('',#2117,.T.);
#2119=ADVANCED_FACE('F382',(#2118),#2093,.F.);
#2120=CARTESIAN_POINT('',(5.,-2.88675134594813,43.27));
#2121=DIRECTION('',(1.,0.,0.));
#2122=DIRECTION('',(0.,-1.,0.));
#2123=AXIS2_PLACEMENT_3D('',#2120,#2121,#2122);
#2124=PLANE('',#2123);
#2125=ORIENTED_EDGE('',*,*,#2054,.T.);
#2126=ORIENTED_EDGE('',*,*,#2115,.F.);
#2127=DIRECTION('',(0.,1.,0.));
#2128=VECTOR('',#2127,1.);
#2129=CARTESIAN_POINT('',(5.,-2.88675134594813,43.27));
#2130=LINE('',#2129,#2128);
#2131=CARTESIAN_POINT('',(5.,-2.88675134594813,43.27));
#2132=VERTEX_POINT('',#2131);
#2133=EDGE_CURVE('E390',#2132,#2108,#2130,.T.);
#2134=ORIENTED_EDGE('',*,*,#2133,.F.);
#2135=DIRECTION('',(0.,0.,1.));
#2136=VECTOR('',#2135,1.);
#2137=CARTESIAN_POINT('',(5.,-2.88675134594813,43.27));
#2138=LINE('',#2137,#2136);
#2139=EDGE_CURVE('E430',#2132,#2053,#2138,.T.);
#2140=ORIENTED_EDGE('',*,*,#2139,.T.);
#2141=EDGE_LOOP('',(#2125,#2126,#2134,#2140));
#2142=FACE_BOUND('',#2141,.T.);
#2143=ADVANCED_FACE('F1744',(#2142),#2124,.F.);
#2144=CARTESIAN_POINT('',(0.,-5.77350269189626,43.27));
#2145=DIRECTION('',(0.5,-0.866025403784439,0.));
#2146=DIRECTION('',(-0.866025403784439,-0.5,0.));
#2147=AXIS2_PLACEMENT_3D('',#2144,#2145,#2146);
#2148=PLANE('',#2147);
#2149=ORIENTED_EDGE('',*,*,#2062,.T.);
#2150=ORIENTED_EDGE('',*,*,#2139,.F.);
#2151=DIRECTION('',(0.866025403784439,0.5,0.));
#2152=VECTOR('',#2151,1.);
#2153=CARTESIAN_POINT('',(0.,-5.77350269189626,43.27));
#2154=LINE('',#2153,#2152);
#2155=CARTESIAN_POINT('',(0.,-5.77350269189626,43.27));
#2156=VERTEX_POINT('',#2155);
#2157=EDGE_CURVE('E413',#2156,#2132,#2154,.T.);
#2158=ORIENTED_EDGE('',*,*,#2157,.F.);
#2159=DIRECTION('',(0.,0.,1.));
#2160=VECTOR('',#2159,1.);
#2161=CARTESIAN_POINT('',(0.,-5.77350269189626,43.27));
#2162=LINE('',#2161,#2160);
#2163=EDGE_CURVE('E432',#2156,#2061,#2162,.T.);
#2164=ORIENTED_EDGE('',*,*,#2163,.T.);
#2165=EDGE_LOOP('',(#2149,#2150,#2158,#2164));
#2166=FACE_BOUND('',#2165,.T.);
#2167=ADVANCED_FACE('F1753',(#2166),#2148,.F.);
#2168=CARTESIAN_POINT('',(-5.,-2.88675134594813,43.27));
#2169=DIRECTION('',(-0.5,-0.866025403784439,0.));
#2170=DIRECTION('',(-0.866025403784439,0.5,0.));
#2171=AXIS2_PLACEMENT_3D('',#2168,#2169,#2170);
#2172=PLANE('',#2171);
#2173=ORIENTED_EDGE('',*,*,#2070,.T.);
#2174=ORIENTED_EDGE('',*,*,#2163,.F.);
#2175=DIRECTION('',(0.866025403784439,-0.5,0.));
#2176=VECTOR('',#2175,1.);
#2177=CARTESIAN_POINT('',(-5.,-2.88675134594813,43.27));
#2178=LINE('',#2177,#2176);
#2179=CARTESIAN_POINT('',(-5.,-2.88675134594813,43.27));
#2180=VERTEX_POINT('',#2179);
#2181=EDGE_CURVE('E410',#2180,#2156,#2178,.T.);
#2182=ORIENTED_EDGE('',*,*,#2181,.F.);
#2183=DIRECTION('',(0.,0.,1.));
#2184=VECTOR('',#2183,1.);
#2185=CARTESIAN_POINT('',(-5.,-2.88675134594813,43.27));
#2186=LINE('',#2185,#2184);
#2187=EDGE_CURVE('E434',#2180,#2069,#2186,.T.);
#2188=ORIENTED_EDGE('',*,*,#2187,.T.);
#2189=EDGE_LOOP('',(#2173,#2174,#2182,#2188));
#2190=FACE_BOUND('',#2189,.T.);
#2191=ADVANCED_FACE('F1763',(#2190),#2172,.F.);
#2192=CARTESIAN_POINT('',(-5.,2.88675134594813,43.27));
#2193=DIRECTION('',(-1.,0.,0.));
#2194=DIRECTION('',(0.,1.,0.));
#2195=AXIS2_PLACEMENT_3D('',#2192,#2193,#2194);
#2196=PLANE('',#2195);
#2197=ORIENTED_EDGE('',*,*,#2078,.T.);
#2198=ORIENTED_EDGE('',*,*,#2187,.F.);
#2199=DIRECTION('',(0.,-1.,0.));
#2200=VECTOR('',#2199,1.);
#2201=CARTESIAN_POINT('',(-5.,2.88675134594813,43.27));
#2202=LINE('',#2201,#2200);
#2203=CARTESIAN_POINT('',(-5.,2.88675134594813,43.27));
#2204=VERTEX_POINT('',#2203);
#2205=EDGE_CURVE('E398',#2204,#2180,#2202,.T.);
#2206=ORIENTED_EDGE('',*,*,#2205,.F.);
#2207=DIRECTION('',(0.,0.,1.));
#2208=VECTOR('',#2207,1.);
#2209=CARTESIAN_POINT('',(-5.,2.88675134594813,43.27));
#2210=LINE('',#2209,#2208);
#2211=EDGE_CURVE('E389',#2204,#2077,#2210,.T.);
#2212=ORIENTED_EDGE('',*,*,#2211,.T.);
#2213=EDGE_LOOP('',(#2197,#2198,#2206,#2212));
#2214=FACE_BOUND('',#2213,.T.);
#2215=ADVANCED_FACE('F1773',(#2214),#2196,.F.);
#2216=CARTESIAN_POINT('',(0.,5.77350269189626,43.27));
#2217=DIRECTION('',(-0.5,0.866025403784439,0.));
#2218=DIRECTION('',(0.866025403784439,0.5,0.));
#2219=AXIS2_PLACEMENT_3D('',#2216,#2217,#2218);
#2220=PLANE('',#2219);
#2221=ORIENTED_EDGE('',*,*,#2084,.T.);
#2222=ORIENTED_EDGE('',*,*,#2211,.F.);
#2223=DIRECTION('',(-0.866025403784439,-0.5,0.));
#2224=VECTOR('',#2223,1.);
#2225=CARTESIAN_POINT('',(0.,5.77350269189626,43.27));
#2226=LINE('',#2225,#2224);
#2227=EDGE_CURVE('E393',#2100,#2204,#2226,.T.);
#2228=ORIENTED_EDGE('',*,*,#2227,.F.);
#2229=ORIENTED_EDGE('',*,*,#2101,.T.);
#2230=EDGE_LOOP('',(#2221,#2222,#2228,#2229));
#2231=FACE_BOUND('',#2230,.T.);
#2232=ADVANCED_FACE('F394',(#2231),#2220,.F.);
#2233=CARTESIAN_POINT('',(0.,5.77350269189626,43.27));
#2234=DIRECTION('',(0.,0.,1.));
#2235=DIRECTION('',(1.,0.,0.));
#2236=AXIS2_PLACEMENT_3D('',#2233,#2234,#2235);
#2237=PLANE('',#2236);
#2238=ORIENTED_EDGE('',*,*,#2109,.T.);
#2239=ORIENTED_EDGE('',*,*,#2227,.T.);
#2240=ORIENTED_EDGE('',*,*,#2205,.T.);
#2241=ORIENTED_EDGE('',*,*,#2181,.T.);
#2242=ORIENTED_EDGE('',*,*,#2157,.T.);
#2243=ORIENTED_EDGE('',*,*,#2133,.T.);
#2244=EDGE_LOOP('',(#2238,#2239,#2240,#2241,#2242,#2243));
#2245=FACE_BOUND('',#2244,.T.);
#2246=ADVANCED_FACE('F400',(#2245),#2237,.T.);
#2247=CARTESIAN_POINT('',(0.,0.,51.27));
#2248=DIRECTION('',(0.,0.,-1.));
#2249=DIRECTION('',(-1.,0.,0.));
#2250=AXIS2_PLACEMENT_3D('',#2247,#2248,#2249);
#2251=CONICAL_SURFACE('',#2250,8.8,1.0471975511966);
#2252=ORIENTED_EDGE('',*,*,#1432,.F.);
#2253=EDGE_LOOP('',(#2252));
#2254=FACE_BOUND('',#2253,.T.);
#2255=ORIENTED_EDGE('',*,*,#2034,.F.);
#2256=EDGE_LOOP('',(#2255));
#2257=FACE_BOUND('',#2256,.T.);
#2258=ADVANCED_FACE('F16',(#2254,#2257),#2251,.T.);
#2259=CLOSED_SHELL('',(#68,#110,#138,#171,#194,#244,#277,#327,#361,#394,#417,#459,#485,#526,
#557,#590,#626,#662,#685,#708,#741,#773,#806,#838,#871,#897,#921,#942,#966,#993,#1017,#1044,
#1083,#1109,#1142,#1174,#1204,#1225,#1249,#1276,#1293,#1300,#1307,#1314,#1321,#1328,#1335,#1342,
#1349,#1356,#1363,#1370,#1377,#1384,#1391,#1398,#1405,#1412,#1419,#1447,#1532,#1538,#1552,#1570,
#1577,#1588,#1595,#1613,#1627,#1638,#1645,#1663,#1670,#1688,#1702,#1713,#1727,#1738,#1752,#1763,
#1770,#1781,#1788,#1799,#1806,#1822,#1829,#1845,#1852,#1858,#1865,#1871,#1878,#1884,#1895,#1901,
#1907,#1913,#1919,#1925,#1931,#1937,#1943,#1949,#1955,#1961,#1967,#1973,#1979,#1985,#1991,#1997,
#2003,#2009,#2021,#2088,#2119,#2143,#2167,#2191,#2215,#2232,#2246,#2258));
#2260=MANIFOLD_SOLID_BREP('B1',#2259);
#2261=ADVANCED_BREP_SHAPE_REPRESENTATION('',(#18,#2260),#14);
#2262=SHAPE_DEFINITION_REPRESENTATION(#9,#2261);
ENDSEC;
END-ISO-10303-21;
